VERSION 5.8 ;
BUSBITCHARS "[]" ;
DIVIDERCHAR "/" ;
UNITS
    DATABASE MICRONS 1000 ;
END UNITS

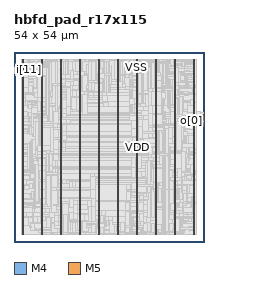
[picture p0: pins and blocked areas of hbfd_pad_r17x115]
MACRO hbfd_pad_r17x115
  FOREIGN hbfd_pad_r17x115 0 0 ;
  CLASS BLOCK ;
  SIZE 54 BY 54 ;
  PIN ck
    DIRECTION INPUT ;
    USE SIGNAL ;
    PORT
      LAYER M4 ;
        RECT  0 47.856 0.084 47.88 ;
    END
  END ck
  PIN i[0]
    DIRECTION INPUT ;
    USE SIGNAL ;
    PORT
      LAYER M4 ;
        RECT  0 47.952 0.084 47.976 ;
    END
  END i[0]
  PIN i[10]
    DIRECTION INPUT ;
    USE SIGNAL ;
    PORT
      LAYER M4 ;
        RECT  0 48.912 0.084 48.936 ;
    END
  END i[10]
  PIN i[11]
    DIRECTION INPUT ;
    USE SIGNAL ;
    PORT
      LAYER M4 ;
        RECT  0 49.008 0.084 49.032 ;
    END
  END i[11]
  PIN i[12]
    DIRECTION INPUT ;
    USE SIGNAL ;
    PORT
      LAYER M4 ;
        RECT  0 49.104 0.084 49.128 ;
    END
  END i[12]
  PIN i[13]
    DIRECTION INPUT ;
    USE SIGNAL ;
    PORT
      LAYER M4 ;
        RECT  0 49.2 0.084 49.224 ;
    END
  END i[13]
  PIN i[14]
    DIRECTION INPUT ;
    USE SIGNAL ;
    PORT
      LAYER M4 ;
        RECT  0 49.296 0.084 49.32 ;
    END
  END i[14]
  PIN i[15]
    DIRECTION INPUT ;
    USE SIGNAL ;
    PORT
      LAYER M4 ;
        RECT  0 49.392 0.084 49.416 ;
    END
  END i[15]
  PIN i[16]
    DIRECTION INPUT ;
    USE SIGNAL ;
    PORT
      LAYER M4 ;
        RECT  0 49.488 0.084 49.512 ;
    END
  END i[16]
  PIN i[1]
    DIRECTION INPUT ;
    USE SIGNAL ;
    PORT
      LAYER M4 ;
        RECT  0 48.048 0.084 48.072 ;
    END
  END i[1]
  PIN i[2]
    DIRECTION INPUT ;
    USE SIGNAL ;
    PORT
      LAYER M4 ;
        RECT  0 48.144 0.084 48.168 ;
    END
  END i[2]
  PIN i[3]
    DIRECTION INPUT ;
    USE SIGNAL ;
    PORT
      LAYER M4 ;
        RECT  0 48.24 0.084 48.264 ;
    END
  END i[3]
  PIN i[4]
    DIRECTION INPUT ;
    USE SIGNAL ;
    PORT
      LAYER M4 ;
        RECT  0 48.336 0.084 48.36 ;
    END
  END i[4]
  PIN i[5]
    DIRECTION INPUT ;
    USE SIGNAL ;
    PORT
      LAYER M4 ;
        RECT  0 48.432 0.084 48.456 ;
    END
  END i[5]
  PIN i[6]
    DIRECTION INPUT ;
    USE SIGNAL ;
    PORT
      LAYER M4 ;
        RECT  0 48.528 0.084 48.552 ;
    END
  END i[6]
  PIN i[7]
    DIRECTION INPUT ;
    USE SIGNAL ;
    PORT
      LAYER M4 ;
        RECT  0 48.624 0.084 48.648 ;
    END
  END i[7]
  PIN i[8]
    DIRECTION INPUT ;
    USE SIGNAL ;
    PORT
      LAYER M4 ;
        RECT  0 48.72 0.084 48.744 ;
    END
  END i[8]
  PIN i[9]
    DIRECTION INPUT ;
    USE SIGNAL ;
    PORT
      LAYER M4 ;
        RECT  0 48.816 0.084 48.84 ;
    END
  END i[9]
  PIN o[0]
    DIRECTION OUTPUT ;
    USE SIGNAL ;
    PORT
      LAYER M4 ;
        RECT  53.916 34.608 54 34.632 ;
    END
  END o[0]
  PIN o[10]
    DIRECTION OUTPUT ;
    USE SIGNAL ;
    PORT
      LAYER M4 ;
        RECT  53.916 35.568 54 35.592 ;
    END
  END o[10]
  PIN o[11]
    DIRECTION OUTPUT ;
    USE SIGNAL ;
    PORT
      LAYER M4 ;
        RECT  53.916 35.664 54 35.688 ;
    END
  END o[11]
  PIN o[12]
    DIRECTION OUTPUT ;
    USE SIGNAL ;
    PORT
      LAYER M4 ;
        RECT  53.916 35.76 54 35.784 ;
    END
  END o[12]
  PIN o[13]
    DIRECTION OUTPUT ;
    USE SIGNAL ;
    PORT
      LAYER M4 ;
        RECT  53.916 35.856 54 35.88 ;
    END
  END o[13]
  PIN o[14]
    DIRECTION OUTPUT ;
    USE SIGNAL ;
    PORT
      LAYER M4 ;
        RECT  53.916 35.952 54 35.976 ;
    END
  END o[14]
  PIN o[15]
    DIRECTION OUTPUT ;
    USE SIGNAL ;
    PORT
      LAYER M4 ;
        RECT  53.916 36.048 54 36.072 ;
    END
  END o[15]
  PIN o[16]
    DIRECTION OUTPUT ;
    USE SIGNAL ;
    PORT
      LAYER M4 ;
        RECT  53.916 36.144 54 36.168 ;
    END
  END o[16]
  PIN o[1]
    DIRECTION OUTPUT ;
    USE SIGNAL ;
    PORT
      LAYER M4 ;
        RECT  53.916 34.704 54 34.728 ;
    END
  END o[1]
  PIN o[2]
    DIRECTION OUTPUT ;
    USE SIGNAL ;
    PORT
      LAYER M4 ;
        RECT  53.916 34.8 54 34.824 ;
    END
  END o[2]
  PIN o[3]
    DIRECTION OUTPUT ;
    USE SIGNAL ;
    PORT
      LAYER M4 ;
        RECT  53.916 34.896 54 34.92 ;
    END
  END o[3]
  PIN o[4]
    DIRECTION OUTPUT ;
    USE SIGNAL ;
    PORT
      LAYER M4 ;
        RECT  53.916 34.992 54 35.016 ;
    END
  END o[4]
  PIN o[5]
    DIRECTION OUTPUT ;
    USE SIGNAL ;
    PORT
      LAYER M4 ;
        RECT  53.916 35.088 54 35.112 ;
    END
  END o[5]
  PIN o[6]
    DIRECTION OUTPUT ;
    USE SIGNAL ;
    PORT
      LAYER M4 ;
        RECT  53.916 35.184 54 35.208 ;
    END
  END o[6]
  PIN o[7]
    DIRECTION OUTPUT ;
    USE SIGNAL ;
    PORT
      LAYER M4 ;
        RECT  53.916 35.28 54 35.304 ;
    END
  END o[7]
  PIN o[8]
    DIRECTION OUTPUT ;
    USE SIGNAL ;
    PORT
      LAYER M4 ;
        RECT  53.916 35.376 54 35.4 ;
    END
  END o[8]
  PIN o[9]
    DIRECTION OUTPUT ;
    USE SIGNAL ;
    PORT
      LAYER M4 ;
        RECT  53.916 35.472 54 35.496 ;
    END
  END o[9]
  PIN rs
    DIRECTION INPUT ;
    USE SIGNAL ;
    PORT
      LAYER M4 ;
        RECT  0 49.584 0.084 49.608 ;
    END
  END rs
  PIN VDD
    DIRECTION INOUT ;
    USE POWER ;
    PORT
      LAYER M5 ;
        RECT  51.192 2.151 51.312 51.849 ;
        RECT  45.792 2.151 45.912 51.849 ;
        RECT  40.392 2.151 40.512 51.849 ;
        RECT  34.992 2.151 35.112 51.849 ;
        RECT  29.592 2.151 29.712 51.849 ;
        RECT  24.192 2.151 24.312 51.849 ;
        RECT  18.792 2.151 18.912 51.849 ;
        RECT  13.392 2.151 13.512 51.849 ;
        RECT  7.992 2.151 8.112 51.849 ;
        RECT  2.592 2.151 2.712 51.849 ;
    END
  END VDD
  PIN VSS
    DIRECTION INOUT ;
    USE GROUND ;
    PORT
      LAYER M5 ;
        RECT  51 2.137 51.12 51.863 ;
        RECT  45.6 2.137 45.72 51.863 ;
        RECT  40.2 2.137 40.32 51.863 ;
        RECT  34.8 2.137 34.92 51.863 ;
        RECT  29.4 2.137 29.52 51.863 ;
        RECT  24 2.137 24.12 51.863 ;
        RECT  18.6 2.137 18.72 51.863 ;
        RECT  13.2 2.137 13.32 51.863 ;
        RECT  7.8 2.137 7.92 51.863 ;
        RECT  2.4 2.137 2.52 51.863 ;
    END
  END VSS
  # OT_OBS_CLOSED layer=M5 d_um=1.536 added=289
  OBS
    LAYER RVTN ;
     RECT  2.16 2.16 51.84 2.295 ;
     RECT  2.16 2.565 51.84 2.835 ;
     RECT  2.16 3.105 51.84 3.375 ;
     RECT  2.16 3.645 51.84 3.915 ;
     RECT  2.16 4.185 51.84 4.455 ;
     RECT  2.16 4.725 51.84 4.995 ;
     RECT  2.16 5.265 51.84 5.535 ;
     RECT  2.16 5.805 51.84 6.075 ;
     RECT  2.16 6.345 51.84 6.615 ;
     RECT  2.16 6.885 51.84 7.155 ;
     RECT  2.16 7.425 51.84 7.695 ;
     RECT  2.16 7.965 51.84 8.235 ;
     RECT  2.16 8.505 51.84 8.775 ;
     RECT  2.16 9.045 51.84 9.315 ;
     RECT  2.16 9.585 51.84 9.855 ;
     RECT  2.16 10.125 51.84 10.395 ;
     RECT  2.16 10.665 51.84 10.935 ;
     RECT  2.16 11.205 51.84 11.475 ;
     RECT  2.16 11.745 51.84 12.015 ;
     RECT  2.16 12.285 51.84 12.555 ;
     RECT  2.16 12.825 51.84 13.095 ;
     RECT  2.16 13.365 51.84 13.635 ;
     RECT  2.16 13.905 51.84 14.175 ;
     RECT  2.16 14.445 51.84 14.715 ;
     RECT  2.16 14.985 51.84 15.255 ;
     RECT  2.16 15.525 51.84 15.795 ;
     RECT  2.16 16.065 51.84 16.335 ;
     RECT  2.16 16.605 51.84 16.875 ;
     RECT  2.16 17.145 51.84 17.415 ;
     RECT  2.16 17.685 51.84 17.955 ;
     RECT  2.16 18.225 51.84 18.495 ;
     RECT  2.16 18.765 51.84 19.035 ;
     RECT  2.16 19.305 51.84 19.575 ;
     RECT  2.16 19.845 51.84 20.115 ;
     RECT  2.16 20.385 51.84 20.655 ;
     RECT  2.16 20.925 51.84 21.195 ;
     RECT  2.16 21.465 51.84 21.735 ;
     RECT  2.16 22.005 51.84 22.275 ;
     RECT  2.16 22.545 51.84 22.815 ;
     RECT  2.16 23.085 51.84 23.355 ;
     RECT  2.16 23.625 51.84 23.895 ;
     RECT  2.16 24.165 51.84 24.435 ;
     RECT  2.16 24.705 51.84 24.975 ;
     RECT  2.16 25.245 51.84 25.515 ;
     RECT  2.16 25.785 51.84 26.055 ;
     RECT  2.16 26.325 51.84 26.595 ;
     RECT  2.16 26.865 51.84 27.135 ;
     RECT  2.16 27.405 51.84 27.675 ;
     RECT  2.16 27.945 51.84 28.215 ;
     RECT  2.16 28.485 51.84 28.755 ;
     RECT  2.16 29.025 51.84 29.295 ;
     RECT  2.16 29.565 51.84 29.835 ;
     RECT  2.16 30.105 51.84 30.375 ;
     RECT  2.16 30.645 51.84 30.915 ;
     RECT  2.16 31.185 51.84 31.455 ;
     RECT  2.16 31.725 51.84 31.995 ;
     RECT  2.16 32.265 51.84 32.535 ;
     RECT  2.16 32.805 51.84 33.075 ;
     RECT  2.16 33.345 51.84 33.615 ;
     RECT  2.16 33.885 51.84 34.155 ;
     RECT  2.16 34.425 51.84 34.695 ;
     RECT  2.16 34.965 51.84 35.235 ;
     RECT  2.16 35.505 51.84 35.775 ;
     RECT  2.16 36.045 51.84 36.315 ;
     RECT  2.16 36.585 51.84 36.855 ;
     RECT  2.16 37.125 51.84 37.395 ;
     RECT  2.16 37.665 51.84 37.935 ;
     RECT  2.16 38.205 51.84 38.475 ;
     RECT  2.16 38.745 51.84 39.015 ;
     RECT  2.16 39.285 51.84 39.555 ;
     RECT  2.16 39.825 51.84 40.095 ;
     RECT  2.16 40.365 51.84 40.635 ;
     RECT  2.16 40.905 51.84 41.175 ;
     RECT  2.16 41.445 51.84 41.715 ;
     RECT  2.16 41.985 51.84 42.255 ;
     RECT  2.16 42.525 51.84 42.795 ;
     RECT  2.16 43.065 51.84 43.335 ;
     RECT  2.16 43.605 51.84 43.875 ;
     RECT  2.16 44.145 51.84 44.415 ;
     RECT  2.16 44.685 51.84 44.955 ;
     RECT  2.16 45.225 51.84 45.495 ;
     RECT  2.16 45.765 51.84 46.035 ;
     RECT  2.16 46.305 51.84 46.575 ;
     RECT  2.16 46.845 51.84 47.115 ;
     RECT  2.16 47.385 51.84 47.655 ;
     RECT  2.16 47.925 51.84 48.195 ;
     RECT  2.16 48.465 51.84 48.735 ;
     RECT  2.16 49.005 51.84 49.275 ;
     RECT  2.16 49.545 51.84 49.815 ;
     RECT  2.16 50.085 51.84 50.355 ;
     RECT  2.16 50.625 51.84 50.895 ;
     RECT  2.16 51.165 51.84 51.435 ;
     RECT  2.16 51.705 51.84 51.84 ;
    LAYER RVTP ;
     RECT  2.16 2.295 51.84 2.565 ;
     RECT  2.16 2.835 51.84 3.105 ;
     RECT  2.16 3.375 51.84 3.645 ;
     RECT  2.16 3.915 51.84 4.185 ;
     RECT  2.16 4.455 51.84 4.725 ;
     RECT  2.16 4.995 51.84 5.265 ;
     RECT  2.16 5.535 51.84 5.805 ;
     RECT  2.16 6.075 51.84 6.345 ;
     RECT  2.16 6.615 51.84 6.885 ;
     RECT  2.16 7.155 51.84 7.425 ;
     RECT  2.16 7.695 51.84 7.965 ;
     RECT  2.16 8.235 51.84 8.505 ;
     RECT  2.16 8.775 51.84 9.045 ;
     RECT  2.16 9.315 51.84 9.585 ;
     RECT  2.16 9.855 51.84 10.125 ;
     RECT  2.16 10.395 51.84 10.665 ;
     RECT  2.16 10.935 51.84 11.205 ;
     RECT  2.16 11.475 51.84 11.745 ;
     RECT  2.16 12.015 51.84 12.285 ;
     RECT  2.16 12.555 51.84 12.825 ;
     RECT  2.16 13.095 51.84 13.365 ;
     RECT  2.16 13.635 51.84 13.905 ;
     RECT  2.16 14.175 51.84 14.445 ;
     RECT  2.16 14.715 51.84 14.985 ;
     RECT  2.16 15.255 51.84 15.525 ;
     RECT  2.16 15.795 51.84 16.065 ;
     RECT  2.16 16.335 51.84 16.605 ;
     RECT  2.16 16.875 51.84 17.145 ;
     RECT  2.16 17.415 51.84 17.685 ;
     RECT  2.16 17.955 51.84 18.225 ;
     RECT  2.16 18.495 51.84 18.765 ;
     RECT  2.16 19.035 51.84 19.305 ;
     RECT  2.16 19.575 51.84 19.845 ;
     RECT  2.16 20.115 51.84 20.385 ;
     RECT  2.16 20.655 51.84 20.925 ;
     RECT  2.16 21.195 51.84 21.465 ;
     RECT  2.16 21.735 51.84 22.005 ;
     RECT  2.16 22.275 51.84 22.545 ;
     RECT  2.16 22.815 51.84 23.085 ;
     RECT  2.16 23.355 51.84 23.625 ;
     RECT  2.16 23.895 51.84 24.165 ;
     RECT  2.16 24.435 51.84 24.705 ;
     RECT  2.16 24.975 51.84 25.245 ;
     RECT  2.16 25.515 51.84 25.785 ;
     RECT  2.16 26.055 51.84 26.325 ;
     RECT  2.16 26.595 51.84 26.865 ;
     RECT  2.16 27.135 51.84 27.405 ;
     RECT  2.16 27.675 51.84 27.945 ;
     RECT  2.16 28.215 51.84 28.485 ;
     RECT  2.16 28.755 51.84 29.025 ;
     RECT  2.16 29.295 51.84 29.565 ;
     RECT  2.16 29.835 51.84 30.105 ;
     RECT  2.16 30.375 51.84 30.645 ;
     RECT  2.16 30.915 51.84 31.185 ;
     RECT  2.16 31.455 51.84 31.725 ;
     RECT  2.16 31.995 51.84 32.265 ;
     RECT  2.16 32.535 51.84 32.805 ;
     RECT  2.16 33.075 51.84 33.345 ;
     RECT  2.16 33.615 51.84 33.885 ;
     RECT  2.16 34.155 51.84 34.425 ;
     RECT  2.16 34.695 51.84 34.965 ;
     RECT  2.16 35.235 51.84 35.505 ;
     RECT  2.16 35.775 51.84 36.045 ;
     RECT  2.16 36.315 51.84 36.585 ;
     RECT  2.16 36.855 51.84 37.125 ;
     RECT  2.16 37.395 51.84 37.665 ;
     RECT  2.16 37.935 51.84 38.205 ;
     RECT  2.16 38.475 51.84 38.745 ;
     RECT  2.16 39.015 51.84 39.285 ;
     RECT  2.16 39.555 51.84 39.825 ;
     RECT  2.16 40.095 51.84 40.365 ;
     RECT  2.16 40.635 51.84 40.905 ;
     RECT  2.16 41.175 51.84 41.445 ;
     RECT  2.16 41.715 51.84 41.985 ;
     RECT  2.16 42.255 51.84 42.525 ;
     RECT  2.16 42.795 51.84 43.065 ;
     RECT  2.16 43.335 51.84 43.605 ;
     RECT  2.16 43.875 51.84 44.145 ;
     RECT  2.16 44.415 51.84 44.685 ;
     RECT  2.16 44.955 51.84 45.225 ;
     RECT  2.16 45.495 51.84 45.765 ;
     RECT  2.16 46.035 51.84 46.305 ;
     RECT  2.16 46.575 51.84 46.845 ;
     RECT  2.16 47.115 51.84 47.385 ;
     RECT  2.16 47.655 51.84 47.925 ;
     RECT  2.16 48.195 51.84 48.465 ;
     RECT  2.16 48.735 51.84 49.005 ;
     RECT  2.16 49.275 51.84 49.545 ;
     RECT  2.16 49.815 51.84 50.085 ;
     RECT  2.16 50.355 51.84 50.625 ;
     RECT  2.16 50.895 51.84 51.165 ;
     RECT  2.16 51.435 51.84 51.705 ;
    LAYER M1 ;
     RECT  2.16 2.151 51.84 51.849 ;
    LAYER M2 ;
     RECT  0.103 47.862 0.499 47.88 ;
     RECT  0.499 47.736 0.535 47.88 ;
     RECT  0.535 47.466 2.16 48.456 ;
     RECT  2.16 2.151 18.823 51.849 ;
     RECT  18.823 2.106 24.251 51.849 ;
     RECT  24.251 2.151 29.083 51.849 ;
     RECT  29.083 2.106 37.067 51.849 ;
     RECT  37.067 2.151 51.84 51.849 ;
     RECT  51.84 34.164 52.979 37.044 ;
     RECT  52.979 34.164 53.015 36.774 ;
     RECT  53.015 36.018 53.051 36.774 ;
     RECT  53.015 34.164 53.087 34.758 ;
     RECT  53.051 36.054 53.843 36.774 ;
     RECT  53.843 36.126 53.879 36.774 ;
     RECT  53.087 34.164 53.915 34.182 ;
     RECT  53.879 36.126 53.915 36.144 ;
    LAYER M3 ;
     RECT  18.828 2.101 18.846 2.143 ;
     RECT  24.228 2.101 24.246 2.143 ;
     RECT  29.088 2.101 29.106 2.143 ;
     RECT  7.815 2.143 7.905 2.191 ;
     RECT  18.615 2.143 18.846 2.191 ;
     RECT  24.015 2.143 24.246 2.191 ;
     RECT  16.668 2.191 16.686 2.227 ;
     RECT  22.356 2.191 22.374 2.227 ;
     RECT  34.815 2.143 34.905 2.227 ;
     RECT  40.215 2.143 40.305 2.227 ;
     RECT  45.615 2.143 45.705 2.227 ;
     RECT  22.212 2.227 23.058 2.251 ;
     RECT  23.976 2.191 24.246 2.251 ;
     RECT  16.344 2.227 16.686 2.263 ;
     RECT  22.212 2.251 23.13 2.263 ;
     RECT  23.976 2.251 24.39 2.263 ;
     RECT  37.044 2.101 37.062 2.263 ;
     RECT  40.215 2.227 40.338 2.263 ;
     RECT  45.615 2.227 46.17 2.263 ;
     RECT  29.088 2.143 29.505 2.293 ;
     RECT  28.656 2.293 29.505 2.299 ;
     RECT  30.348 2.101 30.366 2.299 ;
     RECT  36.324 2.263 37.062 2.299 ;
     RECT  40.215 2.263 40.554 2.299 ;
     RECT  31.608 2.263 31.626 2.335 ;
     RECT  7.596 2.191 7.905 2.371 ;
     RECT  10.26 2.191 10.278 2.371 ;
     RECT  13.215 2.143 13.305 2.371 ;
     RECT  15.84 2.263 16.686 2.371 ;
     RECT  18.252 2.191 18.846 2.371 ;
     RECT  31.464 2.335 31.626 2.371 ;
     RECT  32.544 2.227 32.562 2.371 ;
     RECT  34.236 2.227 34.905 2.371 ;
     RECT  40.14 2.299 40.554 2.371 ;
     RECT  45.615 2.263 46.314 2.371 ;
     RECT  2.415 2.143 2.505 2.413 ;
     RECT  51.015 2.143 51.105 2.413 ;
     RECT  33.372 2.371 35.334 2.443 ;
     RECT  36.324 2.299 37.638 2.443 ;
     RECT  15.228 2.371 16.686 2.461 ;
     RECT  18.252 2.371 18.954 2.461 ;
     RECT  45.615 2.371 46.818 2.461 ;
     RECT  25.704 2.371 26.37 2.488 ;
     RECT  27.288 2.299 27.306 2.488 ;
     RECT  28.656 2.299 30.366 2.491 ;
     RECT  33.372 2.443 37.638 2.497 ;
     RECT  40.14 2.371 43.29 2.497 ;
     RECT  10.26 2.371 10.566 2.533 ;
     RECT  11.448 2.497 11.466 2.533 ;
     RECT  31.464 2.371 32.562 2.533 ;
     RECT  33.372 2.497 37.746 2.533 ;
     RECT  39.888 2.497 43.29 2.533 ;
     RECT  45.615 2.461 47.43 2.533 ;
     RECT  38.736 2.497 38.754 2.569 ;
     RECT  39.6 2.533 43.29 2.569 ;
     RECT  45.615 2.533 48.222 2.569 ;
     RECT  7.452 2.371 8.37 2.605 ;
     RECT  9.216 2.371 9.234 2.605 ;
     RECT  12.276 2.461 12.294 2.605 ;
     RECT  13.215 2.371 14.022 2.605 ;
     RECT  20.268 2.497 20.286 2.605 ;
     RECT  21.708 2.263 24.39 2.605 ;
     RECT  25.704 2.488 27.306 2.605 ;
     RECT  44.172 2.461 44.19 2.605 ;
     RECT  45.615 2.569 48.474 2.605 ;
     RECT  6.948 2.605 9.234 2.641 ;
     RECT  10.26 2.533 11.466 2.641 ;
     RECT  12.276 2.605 14.022 2.641 ;
     RECT  15.228 2.461 18.954 2.641 ;
     RECT  19.728 2.605 20.286 2.641 ;
     RECT  21.528 2.605 24.39 2.641 ;
     RECT  25.524 2.605 27.306 2.641 ;
     RECT  28.224 2.491 30.366 2.641 ;
     RECT  31.464 2.533 37.746 2.641 ;
     RECT  38.736 2.569 43.29 2.641 ;
     RECT  44.172 2.605 48.474 2.641 ;
     RECT  12.204 2.641 43.29 2.731 ;
     RECT  44.172 2.641 48.582 2.731 ;
     RECT  6.948 2.641 11.466 2.767 ;
     RECT  12.204 2.731 48.582 2.767 ;
     RECT  6.948 2.767 48.582 3.145 ;
     RECT  49.86 2.875 49.878 3.145 ;
     RECT  51.015 2.413 51.297 3.145 ;
     RECT  5.328 3.145 5.346 3.181 ;
     RECT  6.588 3.145 48.654 3.181 ;
     RECT  49.86 3.145 51.297 3.181 ;
     RECT  5.328 3.181 48.654 3.343 ;
     RECT  4.788 3.343 48.798 3.371 ;
     RECT  5.724 3.371 48.798 3.451 ;
     RECT  49.752 3.181 51.297 3.451 ;
     RECT  4.788 3.371 4.806 4.225 ;
     RECT  4.428 4.225 4.806 4.261 ;
     RECT  4.428 4.261 4.878 4.379 ;
     RECT  4.428 4.379 4.59 4.765 ;
     RECT  4.032 4.765 4.59 4.829 ;
     RECT  4.572 4.829 4.59 5.197 ;
     RECT  5.724 3.451 51.297 5.197 ;
     RECT  4.572 5.197 51.297 5.837 ;
     RECT  4.572 5.837 49.554 5.999 ;
     RECT  3.708 5.575 3.726 6.043 ;
     RECT  3.564 6.043 3.726 6.283 ;
     RECT  2.415 2.413 2.697 6.547 ;
     RECT  3.564 6.283 4.014 6.547 ;
     RECT  4.752 5.999 49.554 6.781 ;
     RECT  50.328 5.837 51.297 6.781 ;
     RECT  2.415 6.547 4.014 7.051 ;
     RECT  4.752 6.781 51.297 7.051 ;
     RECT  2.415 7.051 51.297 7.349 ;
     RECT  2.415 7.349 2.697 8.509 ;
     RECT  3.564 7.349 51.297 8.509 ;
     RECT  2.415 8.509 51.297 9.787 ;
     RECT  2.376 9.787 51.297 10.895 ;
     RECT  2.415 10.895 51.297 11.011 ;
     RECT  2.415 11.011 51.714 11.201 ;
     RECT  2.415 11.201 51.354 12.209 ;
     RECT  2.415 12.209 51.297 13.675 ;
     RECT  2.376 13.675 51.297 13.829 ;
     RECT  2.415 13.829 51.297 16.141 ;
     RECT  2.415 16.141 51.354 16.367 ;
     RECT  2.415 16.367 51.297 17.491 ;
     RECT  2.415 17.491 51.714 17.681 ;
     RECT  2.415 17.681 51.297 19.039 ;
     RECT  2.415 19.039 51.39 19.309 ;
     RECT  2.415 19.309 51.534 19.651 ;
     RECT  2.415 19.651 51.714 19.921 ;
     RECT  2.376 19.921 51.714 20.381 ;
     RECT  2.376 20.381 51.297 20.615 ;
     RECT  2.415 20.615 51.297 24.241 ;
     RECT  2.376 24.241 51.297 24.943 ;
     RECT  2.304 24.943 51.297 25.285 ;
     RECT  2.304 25.285 51.714 25.439 ;
     RECT  2.304 25.439 51.297 26.401 ;
     RECT  2.304 26.401 51.714 26.663 ;
     RECT  2.304 26.663 51.297 30.749 ;
     RECT  2.376 30.749 51.297 32.035 ;
     RECT  2.376 32.035 51.354 32.225 ;
     RECT  2.415 32.225 51.354 32.369 ;
     RECT  2.415 32.369 51.297 32.971 ;
     RECT  2.376 32.971 51.297 33.053 ;
     RECT  2.415 33.053 51.297 33.277 ;
     RECT  2.415 33.277 51.318 33.449 ;
     RECT  53.892 34.159 53.91 34.637 ;
     RECT  52.452 34.501 52.47 34.663 ;
     RECT  52.416 34.663 52.47 34.733 ;
     RECT  52.452 34.733 52.47 34.735 ;
     RECT  52.452 34.735 53.082 34.829 ;
     RECT  52.452 34.829 53.01 34.925 ;
     RECT  2.415 33.449 51.297 34.969 ;
     RECT  2.415 34.969 51.318 35.117 ;
     RECT  52.956 34.925 53.01 35.563 ;
     RECT  2.415 35.117 51.297 35.581 ;
     RECT  2.376 35.581 51.297 35.699 ;
     RECT  53.82 35.467 53.838 35.851 ;
     RECT  52.956 35.563 53.046 35.947 ;
     RECT  52.416 35.947 53.046 36.041 ;
     RECT  53.82 35.851 53.91 36.077 ;
     RECT  53.856 36.077 53.91 36.149 ;
     RECT  52.416 36.041 53.01 36.239 ;
     RECT  52.956 36.239 53.01 36.509 ;
     RECT  53.856 36.149 53.874 36.779 ;
     RECT  2.415 35.699 51.297 36.931 ;
     RECT  52.956 36.509 52.974 37.049 ;
     RECT  2.376 36.931 51.297 38.669 ;
     RECT  2.415 38.669 51.297 39.595 ;
     RECT  2.415 39.595 51.714 39.749 ;
     RECT  2.415 39.749 51.297 40.027 ;
     RECT  2.376 40.027 51.297 40.289 ;
     RECT  2.415 40.289 51.297 41.791 ;
     RECT  2.415 41.791 51.354 42.061 ;
     RECT  2.415 42.061 51.462 42.179 ;
     RECT  2.415 42.179 51.297 43.645 ;
     RECT  2.415 43.645 51.39 43.915 ;
     RECT  2.415 43.915 51.534 44.339 ;
     RECT  2.415 44.339 51.39 44.375 ;
     RECT  2.415 44.375 51.297 44.491 ;
     RECT  2.376 44.491 51.297 45.455 ;
     RECT  2.415 45.455 51.297 45.535 ;
     RECT  2.415 45.535 51.354 46.139 ;
     RECT  2.415 46.139 51.297 47.155 ;
     RECT  2.34 47.155 51.297 47.579 ;
     RECT  3.78 47.579 51.297 47.687 ;
     RECT  0.54 47.461 0.558 47.731 ;
     RECT  0.504 47.731 0.558 47.857 ;
     RECT  2.34 47.579 2.898 47.885 ;
     RECT  7.416 47.687 51.297 47.885 ;
     RECT  0.108 47.857 0.558 47.981 ;
     RECT  3.78 47.687 6.642 47.993 ;
     RECT  0.504 47.981 0.558 48.173 ;
     RECT  2.34 47.885 2.826 48.235 ;
     RECT  26.964 47.885 51.297 48.425 ;
     RECT  3.924 47.993 6.642 48.469 ;
     RECT  7.416 47.885 26.226 48.469 ;
     RECT  0.54 48.173 0.558 48.557 ;
     RECT  3.924 48.469 26.226 48.811 ;
     RECT  2.304 48.235 2.826 48.937 ;
     RECT  3.636 48.811 26.226 48.937 ;
     RECT  2.304 48.937 26.226 49.099 ;
     RECT  27 48.425 51.297 49.199 ;
     RECT  2.268 49.099 26.226 49.307 ;
     RECT  2.304 49.307 26.226 49.315 ;
     RECT  27 49.199 48.402 49.315 ;
     RECT  2.304 49.315 48.402 49.775 ;
     RECT  2.34 49.775 48.402 49.906 ;
     RECT  45.288 49.906 48.402 49.963 ;
     RECT  49.212 49.199 51.297 49.963 ;
     RECT  2.34 49.906 44.514 50.153 ;
     RECT  2.34 50.153 44.37 50.315 ;
     RECT  45.288 49.963 51.297 50.521 ;
     RECT  45.288 50.521 51.354 50.701 ;
     RECT  45.216 50.701 51.39 50.819 ;
     RECT  2.376 50.315 44.37 50.963 ;
     RECT  3.708 50.963 25.794 51.089 ;
     RECT  26.784 50.963 44.37 51.089 ;
     RECT  2.376 50.963 2.697 51.149 ;
     RECT  3.708 51.089 25.722 51.233 ;
     RECT  26.892 51.089 44.37 51.241 ;
     RECT  3.708 51.233 15.57 51.293 ;
     RECT  26.892 51.241 44.442 51.341 ;
     RECT  3.708 51.293 15.534 51.359 ;
     RECT  16.416 51.233 25.722 51.359 ;
     RECT  32.724 51.341 44.442 51.359 ;
     RECT  45.216 50.819 51.297 51.359 ;
     RECT  5.544 51.359 5.814 51.395 ;
     RECT  14.544 51.359 15.426 51.395 ;
     RECT  26.892 51.341 31.986 51.395 ;
     RECT  16.668 51.359 19.242 51.437 ;
     RECT  6.912 51.359 8.226 51.467 ;
     RECT  29.016 51.395 31.914 51.467 ;
     RECT  42.192 51.359 42.354 51.503 ;
     RECT  45.468 51.359 51.297 51.503 ;
     RECT  21.204 51.359 25.722 51.539 ;
     RECT  34.092 51.359 41.418 51.539 ;
     RECT  2.415 51.149 2.697 51.587 ;
     RECT  29.016 51.467 30.33 51.587 ;
     RECT  45.468 51.503 47.61 51.587 ;
     RECT  51.015 51.503 51.297 51.587 ;
     RECT  3.708 51.359 4.734 51.629 ;
     RECT  5.544 51.395 5.562 51.629 ;
     RECT  7.056 51.467 8.226 51.629 ;
     RECT  9 51.359 12.438 51.629 ;
     RECT  14.544 51.395 15.39 51.629 ;
     RECT  19.98 51.359 20.214 51.629 ;
     RECT  21.276 51.539 25.722 51.629 ;
     RECT  27.036 51.395 28.242 51.629 ;
     RECT  29.016 51.587 29.505 51.629 ;
     RECT  32.724 51.359 33.318 51.629 ;
     RECT  34.092 51.539 39.078 51.629 ;
     RECT  39.888 51.539 41.418 51.629 ;
     RECT  42.192 51.503 42.21 51.629 ;
     RECT  48.492 51.503 50.13 51.629 ;
     RECT  27.432 51.629 28.098 51.635 ;
     RECT  11.052 51.629 12.366 51.665 ;
     RECT  14.544 51.629 15.246 51.665 ;
     RECT  16.776 51.437 19.242 51.665 ;
     RECT  23.112 51.629 25.614 51.665 ;
     RECT  27.432 51.635 27.774 51.665 ;
     RECT  31.104 51.467 31.806 51.665 ;
     RECT  43.236 51.359 44.442 51.665 ;
     RECT  49.176 51.629 50.13 51.665 ;
     RECT  23.112 51.665 25.47 51.677 ;
     RECT  45.468 51.587 45.705 51.677 ;
     RECT  46.584 51.587 47.61 51.677 ;
     RECT  49.392 51.665 49.698 51.701 ;
     RECT  16.776 51.665 18.705 51.737 ;
     RECT  23.112 51.677 23.13 51.737 ;
     RECT  24.015 51.677 24.354 51.737 ;
     RECT  25.128 51.677 25.47 51.737 ;
     RECT  30.312 51.587 30.33 51.737 ;
     RECT  9 51.629 9.666 51.773 ;
     RECT  11.16 51.665 12.366 51.773 ;
     RECT  27.432 51.665 27.45 51.773 ;
     RECT  34.668 51.629 34.905 51.773 ;
     RECT  35.748 51.629 35.766 51.773 ;
     RECT  36.684 51.629 36.702 51.773 ;
     RECT  41.4 51.629 41.418 51.773 ;
     RECT  43.884 51.665 44.442 51.773 ;
     RECT  7.056 51.629 7.905 51.809 ;
     RECT  9 51.773 9.018 51.809 ;
     RECT  11.484 51.773 11.502 51.809 ;
     RECT  13.215 51.359 13.77 51.809 ;
     RECT  16.776 51.737 17.442 51.809 ;
     RECT  25.452 51.737 25.47 51.809 ;
     RECT  31.788 51.665 31.806 51.809 ;
     RECT  37.62 51.629 37.638 51.809 ;
     RECT  47.052 51.677 47.61 51.809 ;
     RECT  49.68 51.701 49.698 51.809 ;
     RECT  2.415 51.587 2.505 51.857 ;
     RECT  7.815 51.809 7.905 51.857 ;
     RECT  13.215 51.809 13.305 51.857 ;
     RECT  18.615 51.737 18.705 51.857 ;
     RECT  24.015 51.737 24.105 51.857 ;
     RECT  29.415 51.629 29.505 51.857 ;
     RECT  34.815 51.773 34.905 51.857 ;
     RECT  40.215 51.629 40.305 51.857 ;
     RECT  45.615 51.677 45.705 51.857 ;
     RECT  51.015 51.587 51.105 51.857 ;
    LAYER M4 ;
     RECT  2.365 13.68 2.408 13.704 ;
     RECT  2.401 26.112 2.408 26.136 ;
     RECT  2.365 27.888 2.408 27.912 ;
     RECT  2.365 33.024 2.408 33.048 ;
     RECT  2.365 40.032 2.408 40.056 ;
     RECT  0.084 47.856 2.408 47.88 ;
     RECT  0.06 47.88 2.408 47.952 ;
     RECT  0.084 47.952 2.408 47.976 ;
     RECT  0.06 47.976 2.408 48.048 ;
     RECT  0.084 48.048 2.408 48.072 ;
     RECT  0.06 48.072 2.408 48.144 ;
     RECT  0.084 48.144 2.408 48.168 ;
     RECT  0.06 48.168 2.408 48.24 ;
     RECT  0.084 48.24 2.408 48.264 ;
     RECT  0.06 48.264 2.408 48.336 ;
     RECT  0.084 48.336 2.408 48.36 ;
     RECT  0.06 48.36 2.408 48.432 ;
     RECT  0.084 48.432 2.408 48.456 ;
     RECT  0.06 48.456 2.408 48.528 ;
     RECT  0.084 48.528 2.408 48.552 ;
     RECT  0.06 48.552 2.408 48.624 ;
     RECT  0.084 48.624 2.408 48.648 ;
     RECT  0.06 48.648 2.408 48.72 ;
     RECT  0.084 48.72 2.408 48.744 ;
     RECT  0.06 48.744 2.408 48.816 ;
     RECT  0.084 48.816 2.408 48.84 ;
     RECT  0.06 48.84 2.408 48.912 ;
     RECT  0.084 48.912 2.408 48.936 ;
     RECT  0.06 48.936 2.408 49.008 ;
     RECT  0.084 49.008 2.408 49.032 ;
     RECT  0.06 49.032 2.408 49.104 ;
     RECT  0.084 49.104 2.408 49.128 ;
     RECT  0.06 49.128 2.408 49.2 ;
     RECT  0.084 49.2 2.408 49.224 ;
     RECT  0.06 49.224 2.408 49.296 ;
     RECT  0.084 49.296 2.408 49.32 ;
     RECT  0.06 49.32 2.408 49.392 ;
     RECT  0.084 49.392 2.408 49.416 ;
     RECT  0.06 49.416 2.408 49.488 ;
     RECT  0.084 49.488 2.408 49.512 ;
     RECT  0.06 49.512 2.408 49.584 ;
     RECT  0.084 49.584 2.408 49.608 ;
     RECT  2.365 51.12 2.408 51.144 ;
     RECT  2.408 2.148 2.512 51.852 ;
     RECT  2.512 2.418 2.704 51.582 ;
     RECT  2.704 47.328 2.801 50.136 ;
     RECT  2.704 26.112 2.819 26.808 ;
     RECT  2.819 26.112 2.837 26.76 ;
     RECT  2.704 14.832 2.917 16.44 ;
     RECT  2.917 15.984 2.953 16.44 ;
     RECT  2.704 38.736 3.299 41.064 ;
     RECT  2.704 42.048 3.436 42.216 ;
     RECT  2.704 33.024 3.629 33.048 ;
     RECT  2.704 35.568 3.701 37.176 ;
     RECT  3.299 38.736 3.701 40.296 ;
     RECT  2.917 14.832 3.733 14.856 ;
     RECT  2.704 27.84 3.733 27.912 ;
     RECT  2.704 51.12 3.737 51.144 ;
     RECT  2.704 30.72 3.769 31.368 ;
     RECT  2.704 10.224 3.773 10.536 ;
     RECT  2.837 26.256 3.805 26.76 ;
     RECT  2.704 20.496 3.877 21.528 ;
     RECT  2.704 22.752 3.877 24.36 ;
     RECT  3.805 25.44 3.877 26.76 ;
     RECT  3.733 27.84 3.877 28.008 ;
     RECT  3.733 14.784 3.881 14.856 ;
     RECT  3.697 5.616 3.913 5.64 ;
     RECT  2.801 47.328 3.932 47.88 ;
     RECT  3.701 38.736 3.949 39 ;
     RECT  2.801 49.2 3.949 50.136 ;
     RECT  3.913 5.616 3.973 6.6 ;
     RECT  3.932 46.752 3.973 47.88 ;
     RECT  3.881 14.832 3.985 14.856 ;
     RECT  2.704 34.176 3.985 34.248 ;
     RECT  3.985 14.832 3.989 15.336 ;
     RECT  3.701 35.568 3.989 36.456 ;
     RECT  3.973 4.8 4.019 7.08 ;
     RECT  3.973 46.752 4.019 48.072 ;
     RECT  3.436 42.192 4.021 42.216 ;
     RECT  2.704 43.296 4.021 44.904 ;
     RECT  4.019 47.76 4.06 48.072 ;
     RECT  4.019 4.8 4.061 4.824 ;
     RECT  3.949 49.2 4.061 50.904 ;
     RECT  3.949 38.208 4.093 39 ;
     RECT  4.021 42.192 4.093 44.904 ;
     RECT  4.093 42.192 4.115 45.48 ;
     RECT  3.985 34.08 4.129 34.248 ;
     RECT  3.989 35.568 4.129 35.592 ;
     RECT  4.061 50.112 4.133 50.904 ;
     RECT  4.115 42.192 4.169 44.472 ;
     RECT  3.769 30.72 4.237 31.656 ;
     RECT  4.201 32.832 4.237 32.856 ;
     RECT  4.093 38.16 4.237 39 ;
     RECT  3.989 15.312 4.273 15.336 ;
     RECT  2.953 16.416 4.273 16.44 ;
     RECT  2.704 17.856 4.273 18.84 ;
     RECT  4.237 30.72 4.273 32.856 ;
     RECT  3.877 20.496 4.309 28.008 ;
     RECT  4.273 17.856 4.345 19.32 ;
     RECT  4.019 6.288 4.385 7.08 ;
     RECT  2.704 12.192 4.385 12.36 ;
     RECT  4.273 15.312 4.417 16.44 ;
     RECT  2.704 13.68 4.453 13.704 ;
     RECT  4.129 34.08 4.457 35.592 ;
     RECT  4.457 35.424 4.493 35.592 ;
     RECT  3.701 40.272 4.565 40.296 ;
     RECT  3.773 10.512 4.669 10.536 ;
     RECT  4.345 17.712 4.705 19.32 ;
     RECT  4.309 20.496 4.705 28.44 ;
     RECT  4.385 12.24 4.741 12.36 ;
     RECT  4.453 13.632 4.741 13.704 ;
     RECT  4.741 12.24 4.957 13.704 ;
     RECT  4.237 37.968 4.957 39 ;
     RECT  4.705 17.712 5.065 28.44 ;
     RECT  4.457 34.08 5.077 34.2 ;
     RECT  4.957 37.968 5.077 39.72 ;
     RECT  4.273 30.672 5.101 32.856 ;
     RECT  5.077 37.584 5.123 39.72 ;
     RECT  4.06 47.76 5.125 47.88 ;
     RECT  5.123 37.584 5.137 38.184 ;
     RECT  5.125 47.76 5.171 48.216 ;
     RECT  4.417 15.312 5.173 16.584 ;
     RECT  5.065 17.712 5.177 29.064 ;
     RECT  5.137 37.344 5.213 38.184 ;
     RECT  5.101 30.624 5.245 32.856 ;
     RECT  5.101 8.304 5.324 8.328 ;
     RECT  4.169 42.432 5.353 44.472 ;
     RECT  4.385 6.288 5.365 6.312 ;
     RECT  4.133 50.496 5.365 50.904 ;
     RECT  5.245 30.096 5.381 32.856 ;
     RECT  5.324 7.584 5.411 8.328 ;
     RECT  5.213 37.344 5.413 37.944 ;
     RECT  5.365 5.664 5.425 6.312 ;
     RECT  4.669 10.512 5.425 10.728 ;
     RECT  4.957 12.24 5.425 14.232 ;
     RECT  5.171 47.856 5.425 48.216 ;
     RECT  5.353 41.712 5.465 44.472 ;
     RECT  5.173 15.312 5.533 16.728 ;
     RECT  5.177 17.712 5.533 23.64 ;
     RECT  5.365 50.496 5.573 51.336 ;
     RECT  5.465 43.92 5.605 44.472 ;
     RECT  4.115 45.456 5.605 45.48 ;
     RECT  4.417 46.512 5.605 46.536 ;
     RECT  5.425 10.512 5.641 14.232 ;
     RECT  5.381 30.096 5.641 33.048 ;
     RECT  5.077 34.032 5.641 34.2 ;
     RECT  5.533 15.312 5.645 23.64 ;
     RECT  5.123 39.168 5.749 39.72 ;
     RECT  5.425 47.856 5.749 48.696 ;
     RECT  5.641 9.84 5.797 14.232 ;
     RECT  5.797 9.456 5.821 14.232 ;
     RECT  5.645 15.312 5.821 22.008 ;
     RECT  5.465 41.712 5.857 42.456 ;
     RECT  5.573 50.496 5.861 50.904 ;
     RECT  5.411 8.304 5.889 8.328 ;
     RECT  5.177 24.864 6.001 29.064 ;
     RECT  5.641 30.096 6.001 34.2 ;
     RECT  5.821 9.456 6.005 22.008 ;
     RECT  6.005 9.456 6.113 10.104 ;
     RECT  5.749 39.168 6.113 39.768 ;
     RECT  6.005 11.376 6.149 22.008 ;
     RECT  6.113 39.264 6.217 39.768 ;
     RECT  5.645 23.04 6.253 23.64 ;
     RECT  6.253 23.04 6.289 23.784 ;
     RECT  5.605 43.92 6.289 46.536 ;
     RECT  5.749 47.856 6.289 49.08 ;
     RECT  6.217 39.264 6.365 39.816 ;
     RECT  6.037 3.84 6.401 3.864 ;
     RECT  4.493 35.424 6.469 35.448 ;
     RECT  5.413 36.624 6.469 37.944 ;
     RECT  5.425 5.664 6.649 7.224 ;
     RECT  6.289 43.92 6.649 49.08 ;
     RECT  6.649 43.824 6.653 49.08 ;
     RECT  6.289 23.04 6.685 23.88 ;
     RECT  6.469 35.424 6.721 37.944 ;
     RECT  6.653 46.56 6.757 49.08 ;
     RECT  5.857 41.04 6.793 42.456 ;
     RECT  5.861 50.688 6.805 50.904 ;
     RECT  6.149 11.52 6.865 22.008 ;
     RECT  6.685 22.992 6.865 23.88 ;
     RECT  6.865 11.52 6.901 23.88 ;
     RECT  6.001 24.864 6.901 34.2 ;
     RECT  6.721 35.184 6.901 37.944 ;
     RECT  6.653 43.824 6.937 45.576 ;
     RECT  6.793 41.04 6.973 42.792 ;
     RECT  6.901 11.52 7.117 37.944 ;
     RECT  6.365 39.312 7.261 39.816 ;
     RECT  6.973 40.896 7.261 42.792 ;
     RECT  7.117 11.232 7.333 37.944 ;
     RECT  7.261 39.312 7.333 42.792 ;
     RECT  6.649 5.616 7.405 7.368 ;
     RECT  6.113 9.792 7.441 10.104 ;
     RECT  7.405 5.616 7.477 7.752 ;
     RECT  7.441 9.696 7.477 10.2 ;
     RECT  7.333 11.232 7.477 42.792 ;
     RECT  6.757 46.56 7.513 49.56 ;
     RECT  6.805 50.688 7.513 51.336 ;
     RECT  7.477 9.696 7.657 42.792 ;
     RECT  7.657 9.264 7.765 42.792 ;
     RECT  7.369 3.936 7.808 3.96 ;
     RECT  7.477 5.28 7.808 7.752 ;
     RECT  7.765 8.976 7.808 42.792 ;
     RECT  6.937 43.776 7.808 45.576 ;
     RECT  7.513 46.56 7.808 51.336 ;
     RECT  7.808 2.148 7.912 51.852 ;
     RECT  7.912 2.418 8.104 51.582 ;
     RECT  8.104 3.936 8.165 7.368 ;
     RECT  8.104 50.544 8.309 51.24 ;
     RECT  8.309 50.544 8.777 51.192 ;
     RECT  8.777 50.832 8.993 51.192 ;
     RECT  8.165 4.08 9.133 7.368 ;
     RECT  8.104 8.496 9.133 49.512 ;
     RECT  9.133 4.08 9.137 49.512 ;
     RECT  9.137 19.968 9.925 49.512 ;
     RECT  8.993 50.832 9.925 51 ;
     RECT  9.925 19.968 10.109 51 ;
     RECT  9.137 4.08 10.465 18.792 ;
     RECT  10.465 3.408 10.501 18.792 ;
     RECT  10.109 39.504 10.537 51 ;
     RECT  10.501 3.168 10.753 18.792 ;
     RECT  10.537 39.504 10.789 51.144 ;
     RECT  10.109 19.968 10.825 38.472 ;
     RECT  10.825 19.872 11.689 38.472 ;
     RECT  10.789 39.504 11.689 51.24 ;
     RECT  10.753 2.64 12.229 18.792 ;
     RECT  11.689 19.872 12.229 51.24 ;
     RECT  12.229 2.64 13.208 51.24 ;
     RECT  13.208 2.148 13.312 51.852 ;
     RECT  13.312 2.418 13.504 51.582 ;
     RECT  13.504 2.784 14.033 51.24 ;
     RECT  14.033 39.072 14.749 51.24 ;
     RECT  14.033 2.784 15.217 37.992 ;
     RECT  14.749 39.072 15.217 51.288 ;
     RECT  15.217 2.784 15.581 51.288 ;
     RECT  15.581 2.784 16.657 51.24 ;
     RECT  16.657 2.784 17.417 51.432 ;
     RECT  17.417 2.784 17.564 51.384 ;
     RECT  17.564 2.688 18.608 51.384 ;
     RECT  18.608 2.148 18.712 51.852 ;
     RECT  18.712 2.418 18.904 51.582 ;
     RECT  18.904 2.88 19.253 51.384 ;
     RECT  19.253 2.88 19.469 51.288 ;
     RECT  19.469 2.88 21.229 51.24 ;
     RECT  21.229 2.832 21.913 51.24 ;
     RECT  21.913 2.832 23.029 51.288 ;
     RECT  23.029 2.496 23.101 51.288 ;
     RECT  23.101 2.256 23.425 51.288 ;
     RECT  23.425 2.256 24.008 51.672 ;
     RECT  24.008 2.148 24.112 51.852 ;
     RECT  24.112 2.256 24.401 51.672 ;
     RECT  24.401 2.352 24.581 51.672 ;
     RECT  24.581 2.352 25.337 51.24 ;
     RECT  25.337 2.352 25.804 51.192 ;
     RECT  25.804 4.464 26.237 51.192 ;
     RECT  26.237 4.752 26.953 51.192 ;
     RECT  25.804 2.352 27.277 3.384 ;
     RECT  26.953 4.752 27.277 51.24 ;
     RECT  27.277 2.352 28.645 51.624 ;
     RECT  28.645 2.304 29.408 51.624 ;
     RECT  29.408 2.148 29.512 51.852 ;
     RECT  29.512 2.304 29.704 51.582 ;
     RECT  29.704 2.304 30.017 51.24 ;
     RECT  30.017 2.352 30.233 51.24 ;
     RECT  30.233 2.88 30.341 51.24 ;
     RECT  30.341 3.024 30.769 51.24 ;
     RECT  30.769 3.024 31.381 51.336 ;
     RECT  31.381 2.784 31.453 51.336 ;
     RECT  31.453 2.736 32.753 51.336 ;
     RECT  32.753 2.736 33.037 51.24 ;
     RECT  33.037 2.544 33.221 51.24 ;
     RECT  33.221 2.784 33.473 51.24 ;
     RECT  33.473 2.88 33.797 51.24 ;
     RECT  33.797 2.88 34.808 3.432 ;
     RECT  33.797 4.416 34.808 51.24 ;
     RECT  34.808 2.148 34.912 51.852 ;
     RECT  34.912 2.418 35.104 51.582 ;
     RECT  35.104 2.448 35.273 51.24 ;
     RECT  35.273 2.448 35.885 3.576 ;
     RECT  35.885 2.832 35.891 3.576 ;
     RECT  35.273 4.656 36.245 51.24 ;
     RECT  35.891 2.88 36.277 3.576 ;
     RECT  36.245 4.656 36.277 50.856 ;
     RECT  36.277 2.88 36.497 50.856 ;
     RECT  36.497 2.928 36.707 50.856 ;
     RECT  36.707 50.592 37.249 50.856 ;
     RECT  37.249 50.592 37.757 51.096 ;
     RECT  36.707 2.928 37.825 49.608 ;
     RECT  37.825 2.88 38.909 49.608 ;
     RECT  38.909 17.136 38.977 49.608 ;
     RECT  37.757 50.688 38.977 51.096 ;
     RECT  38.909 2.88 39.193 16.152 ;
     RECT  39.193 2.784 39.884 16.152 ;
     RECT  38.977 17.136 39.884 51.096 ;
     RECT  39.884 2.784 40.069 51.096 ;
     RECT  40.069 2.256 40.208 51.096 ;
     RECT  40.208 2.148 40.312 51.852 ;
     RECT  40.312 2.256 40.349 51.582 ;
     RECT  40.349 2.418 40.504 51.582 ;
     RECT  40.504 2.784 40.673 51.24 ;
     RECT  40.673 2.832 40.925 51.24 ;
     RECT  40.925 2.832 41.105 50.856 ;
     RECT  41.105 16.08 41.357 50.856 ;
     RECT  41.105 2.832 41.929 15.096 ;
     RECT  41.929 2.64 42.073 15.096 ;
     RECT  41.357 16.08 42.073 50.712 ;
     RECT  42.073 2.64 42.257 50.712 ;
     RECT  42.257 45.12 42.433 50.712 ;
     RECT  42.257 2.64 42.617 44.136 ;
     RECT  42.617 2.64 42.653 37.224 ;
     RECT  42.617 38.688 42.653 44.136 ;
     RECT  42.653 33.552 43.013 37.224 ;
     RECT  42.653 2.64 43.121 32.376 ;
     RECT  43.013 33.552 43.157 36.696 ;
     RECT  42.433 45.12 43.196 50.856 ;
     RECT  42.653 44.112 43.225 44.136 ;
     RECT  43.196 45.12 43.225 51.624 ;
     RECT  43.225 44.112 43.283 51.624 ;
     RECT  42.653 38.688 43.621 43.08 ;
     RECT  43.283 44.112 43.697 50.856 ;
     RECT  43.121 3.024 43.801 32.376 ;
     RECT  43.157 33.552 43.801 34.968 ;
     RECT  43.697 48.24 43.841 50.856 ;
     RECT  43.621 38.208 43.873 43.08 ;
     RECT  43.801 3.024 43.877 34.968 ;
     RECT  43.873 38.016 43.909 43.08 ;
     RECT  43.877 28.416 43.913 34.968 ;
     RECT  43.697 44.112 44.021 46.584 ;
     RECT  43.909 38.016 44.089 43.128 ;
     RECT  43.157 36.336 44.161 36.696 ;
     RECT  44.089 37.968 44.161 43.128 ;
     RECT  43.877 3.024 44.165 27.096 ;
     RECT  44.165 3.024 44.201 20.424 ;
     RECT  43.841 48.24 44.201 48.984 ;
     RECT  44.021 44.16 44.237 46.584 ;
     RECT  44.165 21.552 44.345 27.096 ;
     RECT  43.841 50.016 44.381 50.856 ;
     RECT  43.913 33.648 44.485 34.968 ;
     RECT  44.161 36.336 44.485 43.128 ;
     RECT  44.485 33.648 44.489 43.128 ;
     RECT  44.237 44.16 44.525 46.296 ;
     RECT  44.381 50.016 44.525 50.136 ;
     RECT  44.525 50.016 45.025 50.04 ;
     RECT  43.913 28.416 45.061 32.52 ;
     RECT  44.489 39.024 45.061 43.128 ;
     RECT  44.525 44.16 45.061 46.104 ;
     RECT  44.201 3.024 45.241 7.8 ;
     RECT  44.201 8.832 45.241 20.424 ;
     RECT  45.241 3.024 45.608 20.424 ;
     RECT  44.345 21.552 45.608 26.856 ;
     RECT  45.061 27.888 45.608 32.52 ;
     RECT  44.489 33.648 45.608 38.04 ;
     RECT  45.061 39.024 45.608 46.104 ;
     RECT  44.201 48.24 45.608 48.408 ;
     RECT  45.025 49.872 45.608 50.04 ;
     RECT  45.457 51.648 45.608 51.672 ;
     RECT  45.608 2.148 45.712 51.852 ;
     RECT  45.712 2.418 45.904 51.672 ;
     RECT  45.904 3.024 45.929 29.064 ;
     RECT  45.929 7.968 46.181 29.064 ;
     RECT  46.181 9.84 46.217 29.064 ;
     RECT  45.904 36.336 46.361 50.04 ;
     RECT  45.904 30.048 46.397 35.16 ;
     RECT  46.217 9.84 46.433 23.064 ;
     RECT  46.217 24.192 46.469 29.064 ;
     RECT  45.904 51.456 46.613 51.672 ;
     RECT  46.433 9.84 46.749 22.872 ;
     RECT  46.361 36.336 46.787 44.328 ;
     RECT  46.361 45.408 46.793 50.04 ;
     RECT  46.613 51.456 46.897 51.48 ;
     RECT  46.749 9.84 46.937 19.992 ;
     RECT  46.897 51.36 46.937 51.48 ;
     RECT  46.787 36.336 46.972 44.136 ;
     RECT  46.749 20.976 47.045 22.872 ;
     RECT  46.972 42.528 47.045 44.136 ;
     RECT  45.929 3.024 47.077 6.648 ;
     RECT  46.181 7.968 47.077 8.856 ;
     RECT  47.077 3.024 47.164 8.856 ;
     RECT  46.793 45.408 47.261 48.264 ;
     RECT  47.045 43.92 47.333 44.136 ;
     RECT  47.164 3.024 47.441 6.84 ;
     RECT  46.793 49.44 47.477 50.04 ;
     RECT  47.441 4.176 47.549 6.84 ;
     RECT  46.469 24.24 47.581 29.064 ;
     RECT  47.333 44.112 47.693 44.136 ;
     RECT  46.397 30.144 47.797 35.16 ;
     RECT  46.972 36.336 47.797 41.352 ;
     RECT  47.581 23.856 47.833 29.064 ;
     RECT  47.797 30.144 47.833 41.352 ;
     RECT  46.937 51.36 47.833 51.384 ;
     RECT  47.164 7.92 47.852 8.856 ;
     RECT  46.937 9.84 47.852 18.552 ;
     RECT  47.477 50.016 47.905 50.04 ;
     RECT  47.833 51.168 47.905 51.384 ;
     RECT  47.852 7.92 47.909 18.552 ;
     RECT  47.909 7.92 47.939 16.152 ;
     RECT  47.549 4.176 47.945 6.744 ;
     RECT  47.945 5.28 47.987 6.744 ;
     RECT  47.939 9.744 48.017 16.152 ;
     RECT  47.833 23.856 48.017 41.352 ;
     RECT  47.939 7.92 48.053 8.472 ;
     RECT  47.045 20.976 48.085 22.584 ;
     RECT  47.261 48.24 48.125 48.264 ;
     RECT  48.017 27.888 48.161 41.352 ;
     RECT  48.161 27.888 48.233 39.816 ;
     RECT  47.045 42.528 48.233 42.792 ;
     RECT  47.987 5.28 48.269 6.648 ;
     RECT  48.161 41.328 48.269 41.352 ;
     RECT  48.017 9.744 48.275 13.704 ;
     RECT  46.937 19.536 48.305 19.992 ;
     RECT  48.233 35.04 48.305 39.816 ;
     RECT  47.909 17.472 48.377 18.552 ;
     RECT  47.261 45.984 48.409 47.256 ;
     RECT  47.905 50.016 48.476 51.384 ;
     RECT  47.441 3.024 48.485 3.048 ;
     RECT  48.269 5.28 48.485 6.12 ;
     RECT  48.409 45.6 48.517 47.256 ;
     RECT  48.476 49.968 48.521 51.384 ;
     RECT  48.521 49.968 48.563 51.288 ;
     RECT  48.233 27.888 48.593 33.624 ;
     RECT  48.563 50.016 48.629 51.288 ;
     RECT  48.305 35.04 48.701 36.552 ;
     RECT  48.193 44.208 48.709 44.232 ;
     RECT  48.517 45.6 48.709 47.4 ;
     RECT  48.305 19.728 48.729 19.992 ;
     RECT  48.593 27.888 48.809 31.704 ;
     RECT  48.709 44.208 48.917 47.4 ;
     RECT  48.377 17.568 48.953 18.552 ;
     RECT  48.485 5.28 48.989 5.496 ;
     RECT  48.809 27.888 49.025 31.512 ;
     RECT  48.275 10.512 49.043 13.704 ;
     RECT  48.085 20.976 49.045 23.544 ;
     RECT  48.017 24.96 49.045 26.76 ;
     RECT  48.953 17.568 49.061 18.024 ;
     RECT  49.045 20.976 49.061 26.76 ;
     RECT  48.017 14.736 49.093 16.152 ;
     RECT  48.053 7.92 49.165 7.944 ;
     RECT  49.043 11.376 49.165 13.704 ;
     RECT  49.093 14.736 49.165 16.44 ;
     RECT  49.165 11.376 49.205 16.44 ;
     RECT  49.165 7.92 49.237 8.328 ;
     RECT  48.917 44.208 49.241 47.304 ;
     RECT  48.305 37.584 49.283 39.768 ;
     RECT  48.701 35.136 49.324 35.88 ;
     RECT  49.283 37.584 49.324 37.608 ;
     RECT  49.205 13.68 49.349 16.44 ;
     RECT  49.237 7.104 49.385 8.328 ;
     RECT  49.025 31.488 49.385 31.512 ;
     RECT  49.241 44.208 49.457 45.576 ;
     RECT  49.061 17.568 49.493 17.976 ;
     RECT  49.025 27.888 49.529 30.264 ;
     RECT  48.629 50.88 49.529 51.288 ;
     RECT  48.373 41.568 49.561 41.592 ;
     RECT  48.233 42.768 49.561 42.792 ;
     RECT  49.561 41.568 49.601 42.792 ;
     RECT  49.529 27.888 49.637 30.216 ;
     RECT  49.601 42.192 49.637 42.792 ;
     RECT  49.637 27.888 49.673 28.776 ;
     RECT  47.945 4.176 49.705 4.2 ;
     RECT  49.061 21.984 49.709 26.76 ;
     RECT  49.457 44.208 49.741 44.232 ;
     RECT  49.709 23.232 49.745 26.76 ;
     RECT  49.741 43.92 49.745 44.232 ;
     RECT  48.949 48.624 49.781 48.648 ;
     RECT  49.349 13.824 49.817 16.44 ;
     RECT  49.745 23.232 49.889 24.552 ;
     RECT  49.916 31.968 49.957 31.992 ;
     RECT  48.593 33.024 49.957 33.624 ;
     RECT  48.729 19.728 50.065 19.752 ;
     RECT  49.283 38.832 50.101 39.768 ;
     RECT  50.065 19.584 50.173 19.752 ;
     RECT  49.309 20.832 50.173 20.856 ;
     RECT  50.173 19.584 50.209 20.856 ;
     RECT  49.709 21.984 50.209 22.008 ;
     RECT  49.205 11.376 50.425 12.552 ;
     RECT  49.385 7.92 50.461 8.328 ;
     RECT  49.241 46.752 50.485 47.304 ;
     RECT  50.485 46.656 50.497 47.304 ;
     RECT  49.493 17.568 50.533 17.592 ;
     RECT  50.533 6.768 50.569 6.792 ;
     RECT  49.324 35.136 50.569 35.832 ;
     RECT  50.137 10.224 50.581 10.248 ;
     RECT  50.425 11.376 50.581 12.84 ;
     RECT  50.581 10.224 50.636 12.84 ;
     RECT  49.957 31.968 50.785 33.624 ;
     RECT  49.637 42.192 50.821 42.6 ;
     RECT  49.745 43.92 50.821 43.944 ;
     RECT  49.705 4.176 51.008 4.296 ;
     RECT  48.989 5.28 51.008 5.304 ;
     RECT  50.569 6.768 51.008 6.888 ;
     RECT  50.461 7.92 51.008 8.472 ;
     RECT  50.636 9.552 51.008 12.84 ;
     RECT  49.817 13.824 51.008 16.152 ;
     RECT  50.533 17.568 51.008 18.504 ;
     RECT  50.209 19.584 51.008 22.008 ;
     RECT  49.889 23.712 51.008 24.552 ;
     RECT  49.745 25.584 51.008 26.76 ;
     RECT  49.673 27.888 51.008 27.912 ;
     RECT  49.637 30.144 51.008 30.216 ;
     RECT  50.785 31.92 51.008 33.624 ;
     RECT  50.569 34.752 51.008 35.832 ;
     RECT  50.101 38.832 51.008 40.44 ;
     RECT  50.821 42.192 51.008 43.944 ;
     RECT  49.457 45.552 51.008 45.576 ;
     RECT  50.497 46.656 51.008 47.736 ;
     RECT  49.529 50.88 51.008 51.24 ;
     RECT  51.008 2.148 51.112 51.852 ;
     RECT  51.112 2.418 51.304 51.582 ;
     RECT  51.304 35.088 52.405 35.112 ;
     RECT  52.405 34.704 52.981 35.976 ;
     RECT  52.981 34.704 53.881 36.168 ;
     RECT  53.881 34.608 53.916 34.632 ;
     RECT  53.881 34.632 53.964 34.704 ;
     RECT  53.881 34.704 53.916 34.728 ;
     RECT  53.881 34.728 53.964 34.8 ;
     RECT  53.881 34.8 53.916 34.824 ;
     RECT  53.881 34.824 53.964 34.896 ;
     RECT  53.881 34.896 53.916 34.92 ;
     RECT  53.881 34.92 53.964 34.992 ;
     RECT  53.881 34.992 53.916 35.016 ;
     RECT  53.881 35.016 53.964 35.088 ;
     RECT  53.881 35.088 53.916 35.112 ;
     RECT  53.881 35.112 53.964 35.184 ;
     RECT  53.881 35.184 53.916 35.208 ;
     RECT  53.881 35.208 53.964 35.28 ;
     RECT  53.881 35.28 53.916 35.304 ;
     RECT  53.881 35.304 53.964 35.376 ;
     RECT  53.881 35.376 53.916 35.4 ;
     RECT  53.881 35.4 53.964 35.472 ;
     RECT  53.881 35.472 53.916 35.496 ;
     RECT  53.881 35.496 53.964 35.568 ;
     RECT  53.881 35.568 53.916 35.592 ;
     RECT  53.881 35.592 53.964 35.664 ;
     RECT  53.881 35.664 53.916 35.688 ;
     RECT  53.881 35.688 53.964 35.76 ;
     RECT  53.881 35.76 53.916 35.784 ;
     RECT  53.881 35.784 53.964 35.856 ;
     RECT  53.881 35.856 53.916 35.88 ;
     RECT  53.881 35.88 53.964 35.952 ;
     RECT  53.881 35.952 53.916 35.976 ;
     RECT  53.881 35.976 53.964 36.048 ;
     RECT  53.881 36.048 53.916 36.072 ;
     RECT  53.881 36.072 53.964 36.144 ;
     RECT  53.881 36.144 53.916 36.168 ;
    LAYER M5 ;
     RECT  2.4 2.137 2.52 2.151 ;
     RECT  7.8 2.137 7.92 2.151 ;
     RECT  13.2 2.137 13.32 2.151 ;
     RECT  18.6 2.137 18.72 2.151 ;
     RECT  24 2.137 24.12 2.151 ;
     RECT  29.4 2.137 29.52 2.151 ;
     RECT  34.8 2.137 34.92 2.151 ;
     RECT  40.2 2.137 40.32 2.151 ;
     RECT  45.6 2.137 45.72 2.151 ;
     RECT  51 2.137 51.12 2.151 ;
     RECT  40.2 2.151 40.512 2.245 ;
     RECT  18.6 2.151 18.912 2.677 ;
     RECT  40.08 2.245 40.512 2.819 ;
     RECT  34.8 2.151 35.112 2.821 ;
     RECT  13.2 2.151 13.512 2.869 ;
     RECT  29.4 2.151 29.712 2.965 ;
     RECT  12.816 2.869 13.512 3.109 ;
     RECT  29.4 2.965 30.264 3.109 ;
     RECT  45.6 2.151 45.912 3.109 ;
     RECT  29.088 3.109 30.264 3.251 ;
     RECT  12.816 3.109 13.656 3.347 ;
     RECT  17.616 2.677 18.912 3.347 ;
     RECT  34.8 2.821 35.88 3.587 ;
     RECT  44.976 3.109 45.912 3.635 ;
     RECT  42.144 3.301 42.168 3.685 ;
     RECT  24 2.151 24.312 3.829 ;
     RECT  29.232 3.251 30.264 4.405 ;
     RECT  25.728 4.261 25.752 4.453 ;
     RECT  34.8 3.587 35.496 4.453 ;
     RECT  34.224 4.453 35.496 4.693 ;
     RECT  33.024 4.117 33.048 4.739 ;
     RECT  13.2 3.347 13.656 4.789 ;
     RECT  20.544 3.925 20.568 4.789 ;
     RECT  21.984 4.261 22.008 4.789 ;
     RECT  20.544 4.789 22.008 4.933 ;
     RECT  23.808 3.829 24.312 4.933 ;
     RECT  25.728 4.453 25.992 4.981 ;
     RECT  28.656 4.405 30.264 5.029 ;
     RECT  40.2 2.819 40.512 5.029 ;
     RECT  40.2 5.029 40.632 5.077 ;
     RECT  41.904 3.685 42.168 5.077 ;
     RECT  36.912 4.165 36.936 5.173 ;
     RECT  20.544 4.933 24.312 5.219 ;
     RECT  43.872 5.173 43.896 5.221 ;
     RECT  45.6 3.635 45.912 5.221 ;
     RECT  11.52 3.925 11.544 5.269 ;
     RECT  23.664 5.219 24.312 5.269 ;
     RECT  34.224 4.693 35.928 5.317 ;
     RECT  43.872 5.221 43.992 5.317 ;
     RECT  10.56 5.269 11.544 5.411 ;
     RECT  36.912 5.173 37.272 5.413 ;
     RECT  28.032 5.029 30.264 5.557 ;
     RECT  31.536 2.773 31.56 5.557 ;
     RECT  25.728 4.981 26.136 5.603 ;
     RECT  20.544 5.219 22.008 5.747 ;
     RECT  33.888 5.317 35.928 5.747 ;
     RECT  12.672 4.789 13.656 5.749 ;
     RECT  20.544 5.747 21.096 5.749 ;
     RECT  17.088 5.605 17.112 5.843 ;
     RECT  16.032 3.301 16.056 5.845 ;
     RECT  18.096 3.347 18.912 5.845 ;
     RECT  20.064 5.749 21.096 5.845 ;
     RECT  15.456 5.845 16.056 5.987 ;
     RECT  18.096 5.845 21.096 5.987 ;
     RECT  25.968 5.603 26.136 6.037 ;
     RECT  38.88 5.317 38.904 6.037 ;
     RECT  7.8 2.151 8.112 6.133 ;
     RECT  38.88 6.037 39.096 6.227 ;
     RECT  43.776 5.317 43.992 6.275 ;
     RECT  44.976 5.221 45.912 6.323 ;
     RECT  23.664 5.269 24.408 6.421 ;
     RECT  48.24 5.461 48.264 6.709 ;
     RECT  43.776 6.275 43.896 6.755 ;
     RECT  38.88 6.227 38.904 6.899 ;
     RECT  3.984 4.789 4.008 7.091 ;
     RECT  12.576 5.749 13.656 7.093 ;
     RECT  33.888 5.747 35.64 7.093 ;
     RECT  45.504 6.323 45.912 7.139 ;
     RECT  43.776 6.755 43.8 7.235 ;
     RECT  36.912 5.413 37.656 7.237 ;
     RECT  25.968 6.037 26.76 7.285 ;
     RECT  28.032 5.557 31.56 7.285 ;
     RECT  33.168 7.093 35.64 7.379 ;
     RECT  7.8 6.133 8.856 7.381 ;
     RECT  9.984 6.901 10.008 7.381 ;
     RECT  47.952 6.709 48.264 7.381 ;
     RECT  23.088 6.421 24.408 7.621 ;
     RECT  12.576 7.093 13.896 7.667 ;
     RECT  7.8 7.381 10.008 7.717 ;
     RECT  15.648 5.987 15.672 7.909 ;
     RECT  51 2.151 51.312 7.909 ;
     RECT  18.096 5.987 20.088 7.957 ;
     RECT  21.072 5.987 21.096 7.957 ;
     RECT  33.36 7.379 35.64 8.003 ;
     RECT  47.088 7.381 48.264 8.003 ;
     RECT  18.096 7.957 21.096 8.005 ;
     RECT  36.912 7.237 37.8 8.245 ;
     RECT  5.376 5.653 5.4 8.293 ;
     RECT  11.52 5.411 11.544 8.435 ;
     RECT  7.488 7.717 10.008 8.437 ;
     RECT  7.488 8.437 10.536 8.483 ;
     RECT  15.408 7.909 15.672 8.485 ;
     RECT  16.8 6.421 16.824 8.485 ;
     RECT  33.36 8.003 35.4 8.485 ;
     RECT  33.168 8.485 35.4 8.531 ;
     RECT  33.168 8.531 35.304 8.725 ;
     RECT  36.912 8.245 37.848 8.821 ;
     RECT  23.088 7.621 24.888 8.869 ;
     RECT  25.968 7.285 31.56 8.869 ;
     RECT  33.024 8.725 35.304 8.963 ;
     RECT  36.576 8.821 37.848 8.963 ;
     RECT  44.448 9.061 44.472 9.109 ;
     RECT  18 8.005 21.096 9.155 ;
     RECT  12.72 7.667 13.896 9.349 ;
     RECT  40.2 5.077 42.168 9.349 ;
     RECT  43.968 9.109 44.472 9.395 ;
     RECT  7.488 8.483 8.904 9.445 ;
     RECT  9.984 8.483 10.536 9.445 ;
     RECT  5.376 8.293 5.832 9.491 ;
     RECT  15.408 8.485 16.824 9.731 ;
     RECT  40.08 9.349 42.168 9.731 ;
     RECT  7.488 9.445 10.536 10.067 ;
     RECT  12.144 9.349 13.896 10.067 ;
     RECT  33.168 8.963 35.304 10.069 ;
     RECT  40.08 9.731 42.12 10.115 ;
     RECT  5.376 9.491 5.4 10.501 ;
     RECT  47.904 8.003 48.264 10.501 ;
     RECT  5.376 10.501 5.688 10.547 ;
     RECT  7.488 10.067 9.576 10.547 ;
     RECT  11.328 10.309 11.352 10.547 ;
     RECT  18 9.155 21 10.547 ;
     RECT  36.768 8.963 37.848 10.739 ;
     RECT  50.688 7.909 51.312 10.837 ;
     RECT  44.448 9.395 44.472 10.883 ;
     RECT  47.904 10.501 49.032 10.883 ;
     RECT  50.592 10.837 51.312 10.979 ;
     RECT  12.72 10.067 13.896 11.029 ;
     RECT  15.408 9.731 15.672 11.029 ;
     RECT  40.2 10.115 42.12 11.171 ;
     RECT  33.12 10.069 35.304 11.269 ;
     RECT  33.12 11.269 35.688 11.317 ;
     RECT  48.24 10.883 49.032 11.411 ;
     RECT  12.72 11.029 15.672 11.413 ;
     RECT  23.088 8.869 31.56 11.605 ;
     RECT  18.144 10.547 21 11.701 ;
     RECT  21.984 10.213 22.008 11.701 ;
     RECT  33.072 11.317 35.688 11.701 ;
     RECT  36.768 10.739 37.8 11.701 ;
     RECT  16.8 9.731 16.824 11.749 ;
     RECT  18.144 11.701 22.008 11.749 ;
     RECT  23.088 11.605 31.896 11.795 ;
     RECT  33.072 11.701 37.8 11.843 ;
     RECT  36.768 11.843 37.8 12.085 ;
     RECT  47.232 11.365 47.256 12.131 ;
     RECT  36.768 12.085 38.136 12.179 ;
     RECT  16.8 11.749 22.008 12.227 ;
     RECT  51 10.979 51.312 12.325 ;
     RECT  12.528 11.413 15.672 12.421 ;
     RECT  16.8 12.227 21.624 12.421 ;
     RECT  7.488 10.547 8.856 12.469 ;
     RECT  5.664 10.547 5.688 12.563 ;
     RECT  12.528 12.421 21.624 12.563 ;
     RECT  48.24 11.411 48.264 12.611 ;
     RECT  33.12 11.843 35.688 12.755 ;
     RECT  36.816 12.179 38.136 12.995 ;
     RECT  34.368 12.755 35.688 13.093 ;
     RECT  34.368 13.093 35.832 13.139 ;
     RECT  34.8 13.139 35.832 13.765 ;
     RECT  36.816 12.995 37.656 13.765 ;
     RECT  34.8 13.765 37.656 14.053 ;
     RECT  34.8 14.053 38.568 14.101 ;
     RECT  34.704 14.101 38.568 14.195 ;
     RECT  33.12 12.755 33.384 14.245 ;
     RECT  40.2 11.171 40.512 14.245 ;
     RECT  47.616 14.197 47.64 14.341 ;
     RECT  33.12 14.245 33.432 14.485 ;
     RECT  33.024 14.485 33.432 14.629 ;
     RECT  42.096 11.171 42.12 14.725 ;
     RECT  12.72 12.563 21.624 14.773 ;
     RECT  39.648 14.245 40.512 14.821 ;
     RECT  32.976 14.629 33.432 14.867 ;
     RECT  11.952 14.773 21.624 14.915 ;
     RECT  32.976 14.867 33.384 14.915 ;
     RECT  17.232 14.915 21.624 14.917 ;
     RECT  44.256 14.869 44.28 15.011 ;
     RECT  7.296 12.469 8.856 15.061 ;
     RECT  50.88 12.325 51.312 15.203 ;
     RECT  42.096 14.725 42.744 15.251 ;
     RECT  2.4 2.151 2.712 15.301 ;
     RECT  45.6 7.139 45.912 15.301 ;
     RECT  39.312 14.821 40.512 15.347 ;
     RECT  10.656 14.773 10.68 15.443 ;
     RECT  11.952 14.915 15.768 15.491 ;
     RECT  17.232 14.917 21.816 15.539 ;
     RECT  34.704 14.195 37.656 15.733 ;
     RECT  47.616 14.341 47.688 15.827 ;
     RECT  45.6 15.301 46.584 15.973 ;
     RECT  47.616 15.827 47.64 15.973 ;
     RECT  34.704 15.733 38.424 16.211 ;
     RECT  45.6 15.973 47.64 16.307 ;
     RECT  23.088 11.795 31.848 16.357 ;
     RECT  33.024 14.915 33.384 16.357 ;
     RECT  2.4 15.301 2.904 16.405 ;
     RECT  12.72 15.491 15.768 16.643 ;
     RECT  23.088 16.357 33.384 16.933 ;
     RECT  34.704 16.211 37.464 16.933 ;
     RECT  39.648 15.347 40.512 17.029 ;
     RECT  42.096 15.251 42.12 17.029 ;
     RECT  7.296 15.061 8.904 17.077 ;
     RECT  45.6 16.307 46.584 17.077 ;
     RECT  17.376 15.539 21.816 17.125 ;
     RECT  45.024 17.077 46.584 17.219 ;
     RECT  14.832 16.643 15.768 17.461 ;
     RECT  16.944 17.125 21.816 17.461 ;
     RECT  45.6 17.219 46.584 17.461 ;
     RECT  47.568 16.307 47.64 17.461 ;
     RECT  23.088 16.933 37.464 17.557 ;
     RECT  6.864 17.077 8.904 17.651 ;
     RECT  2.4 16.405 3.432 17.891 ;
     RECT  12.72 16.643 13.8 17.893 ;
     RECT  14.832 17.461 21.816 17.893 ;
     RECT  23.088 17.557 37.704 18.179 ;
     RECT  4.752 18.037 4.776 18.181 ;
     RECT  34.656 18.179 37.704 18.227 ;
     RECT  45.6 17.461 47.64 18.227 ;
     RECT  23.088 18.179 33.624 18.323 ;
     RECT  44.448 17.605 44.472 18.419 ;
     RECT  47.568 18.227 47.64 18.517 ;
     RECT  23.088 18.323 33.528 18.565 ;
     RECT  36.096 18.227 37.464 18.611 ;
     RECT  45.6 18.227 46.584 18.805 ;
     RECT  4.752 18.181 5.736 19.379 ;
     RECT  12.72 17.893 21.816 19.381 ;
     RECT  22.944 18.565 33.528 19.381 ;
     RECT  47.568 18.517 48.504 19.763 ;
     RECT  44.976 18.805 46.584 19.811 ;
     RECT  34.656 18.227 35.112 19.957 ;
     RECT  36.096 18.611 37.32 19.957 ;
     RECT  4.752 19.379 4.776 20.003 ;
     RECT  7.296 17.651 8.904 20.437 ;
     RECT  12.72 19.381 33.528 20.725 ;
     RECT  12.48 20.725 33.528 20.821 ;
     RECT  45.6 19.811 46.584 20.821 ;
     RECT  47.568 19.763 47.64 20.821 ;
     RECT  39.648 17.029 42.12 20.917 ;
     RECT  34.656 19.957 37.32 20.963 ;
     RECT  38.88 20.917 42.12 21.059 ;
     RECT  12.24 20.821 33.528 21.107 ;
     RECT  34.656 20.963 35.112 21.109 ;
     RECT  12.288 21.107 33.528 21.347 ;
     RECT  7.104 20.437 8.904 21.637 ;
     RECT  36.096 20.963 37.32 21.637 ;
     RECT  7.104 21.637 9.432 21.779 ;
     RECT  39.648 21.059 42.12 22.021 ;
     RECT  39.36 22.021 42.12 22.163 ;
     RECT  10.8 20.821 10.824 22.211 ;
     RECT  36.096 21.637 37.416 22.501 ;
     RECT  5.328 22.165 5.352 22.741 ;
     RECT  48.672 19.957 48.696 22.741 ;
     RECT  4.416 22.741 5.352 22.835 ;
     RECT  39.36 22.163 41.256 22.835 ;
     RECT  12.48 21.347 33.528 23.027 ;
     RECT  36.096 22.501 37.608 23.077 ;
     RECT  44.448 22.165 44.472 23.411 ;
     RECT  4.416 22.835 4.44 23.555 ;
     RECT  11.28 23.125 11.304 23.557 ;
     RECT  7.104 21.779 8.856 23.749 ;
     RECT  6.816 23.749 8.856 23.893 ;
     RECT  36.096 23.077 38.232 23.893 ;
     RECT  39.648 22.835 41.256 23.893 ;
     RECT  12.72 23.027 33.528 23.989 ;
     RECT  34.56 21.109 35.112 23.989 ;
     RECT  36.096 23.893 41.256 24.083 ;
     RECT  48.672 22.741 49.08 24.085 ;
     RECT  43.536 24.373 43.56 24.469 ;
     RECT  12.72 23.989 35.112 24.517 ;
     RECT  36.096 24.083 38.088 24.517 ;
     RECT  10.848 23.557 11.304 24.757 ;
     RECT  6.816 23.893 9.144 24.949 ;
     RECT  10.752 24.757 11.304 24.949 ;
     RECT  12.72 24.517 38.088 24.949 ;
     RECT  39.12 24.083 41.256 24.995 ;
     RECT  10.752 24.949 38.088 25.045 ;
     RECT  39.36 24.995 41.256 25.045 ;
     RECT  10.224 25.045 38.088 25.091 ;
     RECT  45.6 20.821 47.64 25.093 ;
     RECT  42.672 24.469 43.56 25.187 ;
     RECT  48.672 24.085 49.32 25.187 ;
     RECT  39.36 25.045 41.688 25.475 ;
     RECT  44.928 25.093 47.64 25.477 ;
     RECT  6.768 24.949 9.144 25.667 ;
     RECT  10.224 25.091 11.304 25.715 ;
     RECT  42.672 25.187 42.696 25.715 ;
     RECT  48.672 25.187 48.696 25.715 ;
     RECT  12.72 25.091 38.088 25.811 ;
     RECT  39.36 25.475 41.256 25.811 ;
     RECT  44.592 25.477 47.64 25.811 ;
     RECT  44.592 25.811 44.616 25.907 ;
     RECT  7.8 25.667 9.144 26.005 ;
     RECT  10.224 25.715 10.248 26.005 ;
     RECT  2.4 17.891 2.712 26.101 ;
     RECT  6.768 25.667 6.792 26.101 ;
     RECT  45.6 25.811 47.64 26.147 ;
     RECT  12.72 25.811 13.704 26.293 ;
     RECT  14.688 25.811 38.088 26.483 ;
     RECT  36.336 26.483 38.088 26.579 ;
     RECT  36.672 26.579 38.088 26.773 ;
     RECT  39.36 25.811 40.512 26.773 ;
     RECT  2.4 26.101 2.808 26.819 ;
     RECT  6.288 26.101 6.792 26.819 ;
     RECT  12.528 26.293 13.704 26.819 ;
     RECT  36.672 26.773 40.512 27.157 ;
     RECT  14.688 26.483 35.112 27.251 ;
     RECT  6.768 26.819 6.792 27.347 ;
     RECT  7.8 26.005 10.248 27.349 ;
     RECT  34.656 27.251 35.112 27.683 ;
     RECT  34.8 27.683 35.112 27.781 ;
     RECT  45.6 26.147 46.2 27.877 ;
     RECT  36.672 27.157 40.632 27.971 ;
     RECT  34.8 27.781 35.208 28.213 ;
     RECT  12.528 26.819 13.656 28.405 ;
     RECT  14.688 27.251 33.672 28.405 ;
     RECT  12.528 28.405 33.672 28.547 ;
     RECT  47.616 26.147 47.64 28.837 ;
     RECT  12.528 28.547 13.752 28.883 ;
     RECT  5.088 27.541 5.112 29.075 ;
     RECT  12.528 28.883 13.656 29.125 ;
     RECT  34.8 28.213 35.352 29.173 ;
     RECT  36.672 27.971 40.512 29.315 ;
     RECT  42.144 29.173 42.168 29.315 ;
     RECT  43.776 27.877 43.8 29.363 ;
     RECT  34.8 29.173 35.4 29.365 ;
     RECT  36.672 29.315 38.088 29.365 ;
     RECT  34.8 29.365 38.088 29.555 ;
     RECT  14.976 28.547 33.672 29.605 ;
     RECT  34.8 29.555 35.352 29.605 ;
     RECT  12.288 29.125 13.656 29.651 ;
     RECT  39.264 29.315 40.512 29.699 ;
     RECT  39.36 29.699 40.512 29.747 ;
     RECT  14.976 29.605 35.352 30.083 ;
     RECT  45.072 27.877 46.2 30.083 ;
     RECT  14.976 30.083 33.336 30.181 ;
     RECT  42.288 30.181 42.312 30.853 ;
     RECT  36.432 29.555 38.088 30.949 ;
     RECT  39.456 29.747 40.512 30.949 ;
     RECT  42.288 30.853 42.408 31.141 ;
     RECT  14.784 30.181 33.336 31.379 ;
     RECT  36.432 30.949 40.512 31.379 ;
     RECT  49.344 30.181 49.368 31.523 ;
     RECT  39.456 31.379 40.512 31.813 ;
     RECT  42.048 31.141 42.408 31.813 ;
     RECT  11.28 25.715 11.304 32.053 ;
     RECT  12.576 29.651 13.656 32.053 ;
     RECT  34.8 30.083 35.352 32.245 ;
     RECT  34.704 32.245 35.352 32.387 ;
     RECT  7.536 27.349 10.248 32.437 ;
     RECT  11.28 32.053 13.656 32.437 ;
     RECT  47.616 28.837 48.264 32.437 ;
     RECT  5.088 30.709 5.496 32.531 ;
     RECT  7.536 32.437 13.656 32.675 ;
     RECT  39.456 31.813 42.408 32.677 ;
     RECT  39.264 32.677 42.408 32.723 ;
     RECT  34.8 32.387 35.352 32.963 ;
     RECT  39.264 32.723 42.312 33.059 ;
     RECT  47.616 32.437 48.36 33.107 ;
     RECT  7.536 32.675 11.304 33.205 ;
     RECT  39.456 33.059 42.312 33.299 ;
     RECT  12.384 32.675 13.656 33.301 ;
     RECT  14.976 31.379 33.336 33.301 ;
     RECT  12.384 33.301 33.336 33.539 ;
     RECT  49.968 31.957 49.992 33.635 ;
     RECT  7.488 33.205 11.304 33.779 ;
     RECT  7.488 33.779 10.248 34.211 ;
     RECT  45.6 30.083 46.2 34.259 ;
     RECT  16.128 33.539 33.336 34.643 ;
     RECT  12.576 33.539 15 34.741 ;
     RECT  16.128 34.643 32.904 34.741 ;
     RECT  43.296 34.165 43.32 34.835 ;
     RECT  47.616 33.107 48.264 34.835 ;
     RECT  36.432 31.379 38.088 34.883 ;
     RECT  47.904 34.835 48.264 34.883 ;
     RECT  34.8 32.963 35.304 35.267 ;
     RECT  7.488 34.211 9.528 35.315 ;
     RECT  12.576 34.741 32.904 35.315 ;
     RECT  36.672 34.883 38.088 35.845 ;
     RECT  14.976 35.315 32.904 35.891 ;
     RECT  48.24 34.883 48.264 35.893 ;
     RECT  7.488 35.315 9.432 35.939 ;
     RECT  47.808 35.893 48.264 35.939 ;
     RECT  34.8 35.267 35.112 35.989 ;
     RECT  7.488 35.939 9.096 36.133 ;
     RECT  14.976 35.891 19.464 36.179 ;
     RECT  20.832 35.891 32.904 36.227 ;
     RECT  39.456 33.299 42.216 36.371 ;
     RECT  6.576 36.133 9.096 36.419 ;
     RECT  12.576 35.315 13.656 36.421 ;
     RECT  39.456 36.371 41.784 36.469 ;
     RECT  21.024 36.227 32.904 36.517 ;
     RECT  21.024 36.517 33.048 36.613 ;
     RECT  34.368 35.989 35.112 36.613 ;
     RECT  5.088 32.531 5.448 36.659 ;
     RECT  34.368 36.613 35.208 36.851 ;
     RECT  21.024 36.613 33.24 36.947 ;
     RECT  11.28 33.779 11.304 37.091 ;
     RECT  47.808 35.939 47.832 37.091 ;
     RECT  6.576 36.419 8.856 37.139 ;
     RECT  16.128 36.179 19.464 37.187 ;
     RECT  36.336 35.845 38.088 37.331 ;
     RECT  17.712 37.187 19.464 37.427 ;
     RECT  7.584 37.139 8.856 37.477 ;
     RECT  16.128 37.187 16.584 37.619 ;
     RECT  12.576 36.421 13.752 38.003 ;
     RECT  44.352 37.045 44.376 38.099 ;
     RECT  34.368 36.851 35.112 38.147 ;
     RECT  49.248 35.845 49.272 38.147 ;
     RECT  5.088 36.659 5.112 38.243 ;
     RECT  12.576 38.003 13.656 38.243 ;
     RECT  7.584 37.477 9.048 38.341 ;
     RECT  21.024 36.947 32.712 38.435 ;
     RECT  36.816 37.331 38.088 38.435 ;
     RECT  7.584 38.341 9.144 38.483 ;
     RECT  16.128 37.619 16.392 38.533 ;
     RECT  34.8 38.147 35.112 38.533 ;
     RECT  39.312 36.469 41.784 38.677 ;
     RECT  13.056 38.243 13.656 38.819 ;
     RECT  34.8 38.533 36.024 39.205 ;
     RECT  21.024 38.435 25.464 39.253 ;
     RECT  20.64 39.253 25.464 39.395 ;
     RECT  34.176 39.205 36.024 39.395 ;
     RECT  21.024 39.395 25.464 39.539 ;
     RECT  2.4 26.819 2.712 39.877 ;
     RECT  6.576 37.139 6.6 39.877 ;
     RECT  7.584 38.483 8.856 39.877 ;
     RECT  26.736 38.435 32.712 40.069 ;
     RECT  14.976 36.179 15 40.405 ;
     RECT  21.024 39.539 25.176 40.405 ;
     RECT  34.176 39.395 35.4 40.835 ;
     RECT  45.6 34.259 45.912 40.885 ;
     RECT  45.6 40.885 46.152 41.027 ;
     RECT  14.88 40.405 15 41.029 ;
     RECT  2.4 39.877 3.288 41.075 ;
     RECT  6.576 39.877 8.856 41.075 ;
     RECT  20.832 40.405 25.176 41.171 ;
     RECT  15.984 38.533 16.392 41.173 ;
     RECT  17.712 37.427 18.912 41.173 ;
     RECT  15.984 41.173 18.912 41.315 ;
     RECT  10.896 41.173 10.92 41.317 ;
     RECT  26.688 40.069 32.712 41.509 ;
     RECT  46.896 41.125 46.92 41.651 ;
     RECT  22.464 41.171 25.176 41.699 ;
     RECT  20.832 41.171 21.096 41.939 ;
     RECT  14.736 41.029 15 42.035 ;
     RECT  2.4 41.075 2.712 42.037 ;
     RECT  37.296 38.435 38.088 42.037 ;
     RECT  36.912 42.037 38.088 42.133 ;
     RECT  34.8 40.835 35.4 42.179 ;
     RECT  13.104 38.819 13.656 42.323 ;
     RECT  14.88 42.035 15 42.419 ;
     RECT  2.4 42.037 3.384 42.421 ;
     RECT  22.608 41.699 25.176 42.467 ;
     RECT  26.16 41.509 32.712 42.467 ;
     RECT  43.056 40.837 43.08 42.467 ;
     RECT  26.16 42.467 26.184 42.515 ;
     RECT  10.512 41.317 10.92 42.659 ;
     RECT  19.968 41.941 19.992 42.755 ;
     RECT  22.752 42.467 25.176 42.803 ;
     RECT  39.168 38.677 41.784 42.803 ;
     RECT  13.2 42.323 13.656 42.805 ;
     RECT  21.024 41.939 21.096 42.949 ;
     RECT  15.984 41.315 16.536 42.997 ;
     RECT  17.712 41.315 18.912 42.997 ;
     RECT  21.024 42.949 21.288 43.139 ;
     RECT  36.672 42.133 38.088 43.139 ;
     RECT  15.984 42.997 18.912 43.187 ;
     RECT  13.2 42.805 13.752 43.285 ;
     RECT  45.6 41.027 45.912 43.285 ;
     RECT  17.712 43.187 18.912 43.379 ;
     RECT  27.456 42.467 32.712 43.379 ;
     RECT  33.792 43.189 33.816 43.381 ;
     RECT  39.36 42.803 41.784 43.523 ;
     RECT  21.024 43.139 21.048 43.525 ;
     RECT  14.976 42.419 15 43.907 ;
     RECT  2.4 42.421 4.104 43.955 ;
     RECT  27.456 43.379 31.752 43.955 ;
     RECT  39.888 43.523 41.784 43.955 ;
     RECT  32.88 43.381 33.816 43.957 ;
     RECT  34.8 42.179 35.112 43.957 ;
     RECT  13.2 43.285 13.8 44.245 ;
     RECT  32.88 43.957 35.112 44.291 ;
     RECT  45.6 43.285 46.776 44.339 ;
     RECT  13.2 44.245 14.664 44.341 ;
     RECT  15.984 43.187 16.536 44.437 ;
     RECT  20.544 43.525 21.048 44.483 ;
     RECT  13.056 44.341 14.664 44.581 ;
     RECT  27.456 43.955 29.712 44.627 ;
     RECT  22.8 42.803 25.176 44.915 ;
     RECT  12.288 44.581 14.664 44.963 ;
     RECT  13.2 44.963 14.664 45.011 ;
     RECT  30.864 43.955 31.752 45.011 ;
     RECT  10.896 42.659 10.92 45.059 ;
     RECT  23.712 44.915 25.176 45.251 ;
     RECT  33.84 44.291 35.112 45.397 ;
     RECT  45.6 44.339 46.008 45.397 ;
     RECT  30.864 45.011 31.368 45.587 ;
     RECT  14.64 45.011 14.664 45.589 ;
     RECT  15.984 44.437 16.968 45.589 ;
     RECT  27.792 44.627 29.712 45.635 ;
     RECT  48.72 44.197 48.744 45.635 ;
     RECT  39.984 43.955 41.784 45.779 ;
     RECT  22.512 45.205 22.536 45.971 ;
     RECT  18.336 43.379 18.912 45.973 ;
     RECT  33.792 45.397 35.112 46.021 ;
     RECT  13.2 45.011 13.512 46.069 ;
     RECT  29.04 45.635 29.712 46.211 ;
     RECT  32.928 46.021 35.112 46.211 ;
     RECT  14.64 45.589 16.968 46.259 ;
     RECT  18.24 45.973 18.912 46.259 ;
     RECT  23.808 45.251 25.176 46.405 ;
     RECT  18.336 46.259 18.912 46.451 ;
     RECT  13.2 46.069 13.656 46.501 ;
     RECT  51 15.203 51.312 46.645 ;
     RECT  31.344 45.587 31.368 46.693 ;
     RECT  4.08 43.955 4.104 46.741 ;
     RECT  50.496 46.645 51.312 46.787 ;
     RECT  21.024 44.483 21.048 46.835 ;
     RECT  6.768 41.075 8.856 47.075 ;
     RECT  33.792 46.211 35.112 47.123 ;
     RECT  27.792 45.635 27.816 47.269 ;
     RECT  31.344 46.693 31.56 47.269 ;
     RECT  48.72 46.645 48.744 47.269 ;
     RECT  33.792 47.123 33.816 47.315 ;
     RECT  6.768 47.075 6.792 47.363 ;
     RECT  40.08 45.779 41.784 47.363 ;
     RECT  7.8 47.075 8.856 47.411 ;
     RECT  48.528 47.269 48.744 47.411 ;
     RECT  32.544 46.741 32.568 47.555 ;
     RECT  21.12 47.413 21.144 47.653 ;
     RECT  21.12 47.653 21.24 47.699 ;
     RECT  31.056 47.269 31.56 47.699 ;
     RECT  18.6 46.451 18.912 47.701 ;
     RECT  13.104 46.501 14.52 47.747 ;
     RECT  3.984 46.741 4.104 47.795 ;
     RECT  13.104 47.747 13.608 47.795 ;
     RECT  21.216 47.699 21.24 47.795 ;
     RECT  34.8 47.123 35.112 47.893 ;
     RECT  36.672 43.139 36.696 47.893 ;
     RECT  23.808 46.405 25.848 47.939 ;
     RECT  27.312 47.269 27.816 47.939 ;
     RECT  40.08 47.363 40.512 47.987 ;
     RECT  34.8 47.893 36.696 48.035 ;
     RECT  3.984 47.795 4.008 48.083 ;
     RECT  41.616 47.363 41.64 48.131 ;
     RECT  5.136 47.749 5.16 48.181 ;
     RECT  5.136 48.181 5.4 48.227 ;
     RECT  18.048 47.701 18.912 48.371 ;
     RECT  31.536 47.699 31.56 48.371 ;
     RECT  20.112 47.317 20.136 48.419 ;
     RECT  15.984 46.259 16.968 48.755 ;
     RECT  13.2 47.795 13.608 48.851 ;
     RECT  16.656 48.755 16.968 48.899 ;
     RECT  13.2 48.851 13.512 48.901 ;
     RECT  13.056 48.901 13.512 49.043 ;
     RECT  24 47.939 25.176 49.235 ;
     RECT  45.6 45.397 46.776 49.475 ;
     RECT  36.672 48.035 36.696 49.859 ;
     RECT  48.528 47.411 48.552 50.003 ;
     RECT  27.792 47.939 27.816 50.195 ;
     RECT  32.304 49.429 32.328 50.243 ;
     RECT  20.592 48.949 20.616 50.341 ;
     RECT  16.656 48.899 16.68 50.387 ;
     RECT  20.592 50.341 21.096 50.387 ;
     RECT  21.072 50.387 21.096 50.579 ;
     RECT  7.8 47.411 8.112 50.677 ;
     RECT  43.824 48.805 43.848 50.771 ;
     RECT  38.064 43.139 38.088 50.867 ;
     RECT  5.376 48.227 5.4 51.347 ;
     RECT  6.816 50.677 8.112 51.347 ;
     RECT  43.248 50.773 43.272 51.635 ;
     RECT  2.4 43.955 2.712 51.849 ;
     RECT  7.8 51.347 8.112 51.849 ;
     RECT  13.2 49.043 13.512 51.849 ;
     RECT  18.6 48.371 18.912 51.849 ;
     RECT  24 49.235 24.312 51.849 ;
     RECT  29.4 46.211 29.712 51.849 ;
     RECT  34.8 48.035 35.112 51.849 ;
     RECT  40.2 47.987 40.512 51.849 ;
     RECT  45.6 49.475 45.912 51.849 ;
     RECT  51 46.787 51.312 51.849 ;
     RECT  2.4 51.849 2.52 51.863 ;
     RECT  7.8 51.849 7.92 51.863 ;
     RECT  13.2 51.849 13.32 51.863 ;
     RECT  18.6 51.849 18.72 51.863 ;
     RECT  24 51.849 24.12 51.863 ;
     RECT  29.4 51.849 29.52 51.863 ;
     RECT  34.8 51.849 34.92 51.863 ;
     RECT  40.2 51.849 40.32 51.863 ;
     RECT  45.6 51.849 45.72 51.863 ;
     RECT  51 51.849 51.12 51.863 ;
     RECT  30.264 2.965 31.536 5.557 ;
     RECT  29.088 3.251 29.232 4.405 ;
     RECT  12.816 3.347 13.2 3.925 ;
     RECT  35.496 3.587 35.88 4.165 ;
     RECT  40.512 3.685 41.904 5.029 ;
     RECT  11.544 3.925 13.2 4.789 ;
     RECT  31.56 4.117 33.024 4.739 ;
     RECT  35.496 4.165 36.912 4.693 ;
     RECT  20.568 4.261 21.984 4.789 ;
     RECT  24.312 4.261 25.728 5.269 ;
     RECT  33.048 4.453 34.224 4.739 ;
     RECT  35.928 4.693 36.912 5.747 ;
     RECT  33.888 4.739 34.224 5.317 ;
     RECT  2.712 4.789 3.984 7.091 ;
     RECT  11.544 4.789 12.672 5.749 ;
     RECT  40.632 5.029 41.904 5.077 ;
     RECT  22.008 5.219 23.664 5.747 ;
     RECT  43.992 5.221 44.976 6.275 ;
     RECT  24.408 5.269 25.728 5.603 ;
     RECT  38.904 5.317 40.2 6.037 ;
     RECT  10.56 5.411 11.52 6.901 ;
     RECT  37.656 5.413 38.88 6.899 ;
     RECT  16.056 5.605 17.088 5.843 ;
     RECT  17.112 5.605 18.096 5.843 ;
     RECT  4.008 5.653 5.376 7.091 ;
     RECT  23.088 5.747 23.664 6.421 ;
     RECT  35.64 5.747 36.912 8.003 ;
     RECT  11.544 5.749 12.576 7.667 ;
     RECT  18.912 5.749 20.064 5.845 ;
     RECT  16.056 5.843 18.096 5.987 ;
     RECT  15.672 5.987 18.096 6.421 ;
     RECT  20.088 5.987 21.072 7.957 ;
     RECT  26.76 6.037 28.032 7.285 ;
     RECT  39.096 6.037 40.2 6.227 ;
     RECT  38.904 6.227 40.2 6.899 ;
     RECT  43.896 6.275 44.976 6.323 ;
     RECT  15.672 6.421 16.8 8.485 ;
     RECT  16.824 6.421 18.096 8.005 ;
     RECT  37.656 6.899 37.848 7.237 ;
     RECT  8.856 6.901 9.984 7.381 ;
     RECT  10.008 6.901 11.52 8.435 ;
     RECT  37.8 7.237 37.848 8.245 ;
     RECT  33.168 7.379 33.36 8.485 ;
     RECT  45.912 7.381 47.088 8.003 ;
     RECT  24.888 7.621 25.968 8.869 ;
     RECT  11.544 7.667 12.72 8.435 ;
     RECT  13.896 7.909 15.408 11.029 ;
     RECT  35.4 8.003 36.912 8.531 ;
     RECT  16.824 8.005 18 10.547 ;
     RECT  10.008 8.435 10.536 8.437 ;
     RECT  12.144 8.435 12.72 9.349 ;
     RECT  8.904 8.483 9.984 9.445 ;
     RECT  35.304 8.531 36.912 8.821 ;
     RECT  31.56 8.725 33.024 8.963 ;
     RECT  35.304 8.821 36.576 8.963 ;
     RECT  33.12 8.963 33.168 10.069 ;
     RECT  35.304 8.963 36.768 11.269 ;
     RECT  44.472 9.061 45.6 10.883 ;
     RECT  21 9.155 21.096 10.213 ;
     RECT  5.4 9.491 5.688 10.501 ;
     RECT  15.672 9.731 16.8 12.421 ;
     RECT  12.144 10.067 12.72 10.309 ;
     RECT  21 10.213 21.984 11.701 ;
     RECT  22.008 10.213 23.088 12.227 ;
     RECT  11.352 10.309 12.72 10.547 ;
     RECT  12.528 10.547 12.72 11.413 ;
     RECT  16.824 10.547 18.144 11.749 ;
     RECT  37.8 10.739 37.848 12.085 ;
     RECT  47.904 10.883 48.24 11.365 ;
     RECT  50.88 10.979 51 12.325 ;
     RECT  35.688 11.269 36.768 11.701 ;
     RECT  31.56 11.317 33.072 11.605 ;
     RECT  45.912 11.365 47.232 12.131 ;
     RECT  47.256 11.365 48.24 12.131 ;
     RECT  31.896 11.605 33.072 11.795 ;
     RECT  31.848 11.795 33.072 11.843 ;
     RECT  31.848 11.843 33.12 14.485 ;
     RECT  35.688 11.843 36.768 12.179 ;
     RECT  35.688 12.179 36.816 13.093 ;
     RECT  21.624 12.227 23.088 14.917 ;
     RECT  33.384 12.755 34.368 13.139 ;
     RECT  37.656 12.995 38.136 14.053 ;
     RECT  35.832 13.093 36.816 13.765 ;
     RECT  33.384 13.139 34.8 14.101 ;
     RECT  33.384 14.101 34.704 14.245 ;
     RECT  33.432 14.245 34.704 14.867 ;
     RECT  31.848 14.485 33.024 14.629 ;
     RECT  31.848 14.629 32.976 14.915 ;
     RECT  10.68 14.773 11.952 15.443 ;
     RECT  33.384 14.867 34.704 16.933 ;
     RECT  42.744 14.869 44.256 15.011 ;
     RECT  44.28 14.869 45.6 15.011 ;
     RECT  15.768 14.915 17.232 15.539 ;
     RECT  31.848 14.915 33.024 16.357 ;
     RECT  21.816 14.917 23.088 18.565 ;
     RECT  46.584 15.301 47.616 15.973 ;
     RECT  39.312 15.347 39.648 15.733 ;
     RECT  38.424 15.733 39.648 16.211 ;
     RECT  37.464 16.211 37.704 17.557 ;
     RECT  46.584 16.307 47.568 17.461 ;
     RECT  13.8 16.643 14.832 17.893 ;
     RECT  15.768 17.125 16.944 17.461 ;
     RECT  45.024 17.219 45.6 17.605 ;
     RECT  44.472 17.605 45.6 18.419 ;
     RECT  33.624 18.179 34.656 18.323 ;
     RECT  35.112 18.227 36.096 19.957 ;
     RECT  46.584 18.227 47.568 20.821 ;
     RECT  33.528 18.323 34.656 21.109 ;
     RECT  44.976 18.419 45.6 18.805 ;
     RECT  21.816 18.565 22.944 19.381 ;
     RECT  47.64 19.763 48.504 19.957 ;
     RECT  47.64 19.957 48.672 25.715 ;
     RECT  10.824 20.821 12.24 21.107 ;
     RECT  35.112 20.963 36.096 24.517 ;
     RECT  39.36 21.059 39.648 22.021 ;
     RECT  10.824 21.107 12.288 21.347 ;
     RECT  33.528 21.109 34.56 23.989 ;
     RECT  9.432 21.637 10.8 21.779 ;
     RECT  44.472 22.165 45.6 23.411 ;
     RECT  39.36 22.835 39.648 23.077 ;
     RECT  12.48 23.027 12.72 23.125 ;
     RECT  38.232 23.077 39.648 23.893 ;
     RECT  11.304 23.125 12.72 24.949 ;
     RECT  38.088 24.083 39.12 24.995 ;
     RECT  41.256 24.469 42.672 25.045 ;
     RECT  38.088 24.995 39.36 26.773 ;
     RECT  9.144 25.045 10.224 26.005 ;
     RECT  41.688 25.045 42.672 25.475 ;
     RECT  11.304 25.091 12.72 26.293 ;
     RECT  43.56 25.093 44.928 25.187 ;
     RECT  44.592 25.187 44.928 25.477 ;
     RECT  41.256 25.475 42.672 25.715 ;
     RECT  6.792 25.667 7.8 27.347 ;
     RECT  10.248 25.715 11.28 32.437 ;
     RECT  13.704 25.811 14.688 26.819 ;
     RECT  40.512 25.811 40.632 27.157 ;
     RECT  44.616 25.811 45.6 25.907 ;
     RECT  46.2 26.147 47.616 34.259 ;
     RECT  11.304 26.293 12.528 29.125 ;
     RECT  35.112 26.483 36.336 26.579 ;
     RECT  35.112 26.579 36.672 27.781 ;
     RECT  13.656 26.819 14.688 28.405 ;
     RECT  33.672 27.251 34.656 27.683 ;
     RECT  7.536 27.347 7.8 27.349 ;
     RECT  33.672 27.683 34.8 29.605 ;
     RECT  35.208 27.781 36.672 28.213 ;
     RECT  43.8 27.877 45.072 29.363 ;
     RECT  35.352 28.213 36.672 29.173 ;
     RECT  13.752 28.547 14.976 28.883 ;
     RECT  13.656 28.883 14.976 30.181 ;
     RECT  11.304 29.125 12.288 29.651 ;
     RECT  35.4 29.173 36.672 29.365 ;
     RECT  38.088 29.315 39.264 29.699 ;
     RECT  35.352 29.555 36.432 32.963 ;
     RECT  11.304 29.651 12.576 32.053 ;
     RECT  38.088 29.699 39.36 29.747 ;
     RECT  38.088 29.747 39.456 30.949 ;
     RECT  33.336 30.083 34.8 32.245 ;
     RECT  13.656 30.181 14.784 31.379 ;
     RECT  48.264 30.181 49.344 31.523 ;
     RECT  13.656 31.379 14.976 33.301 ;
     RECT  38.088 31.379 39.456 32.677 ;
     RECT  48.264 31.523 48.36 32.437 ;
     RECT  49.992 31.957 51 33.635 ;
     RECT  33.336 32.245 34.704 32.387 ;
     RECT  33.336 32.387 34.8 34.643 ;
     RECT  11.304 32.675 12.384 33.539 ;
     RECT  38.088 32.677 39.264 33.059 ;
     RECT  42.312 32.723 42.408 33.299 ;
     RECT  35.304 32.963 36.432 34.883 ;
     RECT  38.088 33.059 39.456 36.469 ;
     RECT  42.216 33.299 42.408 34.165 ;
     RECT  11.304 33.539 12.576 37.091 ;
     RECT  15 33.539 16.128 34.741 ;
     RECT  10.248 33.779 11.28 34.211 ;
     RECT  42.216 34.165 43.296 34.835 ;
     RECT  32.904 34.643 34.8 35.989 ;
     RECT  47.808 34.835 47.904 34.883 ;
     RECT  35.304 34.883 36.672 35.267 ;
     RECT  47.808 34.883 48.24 35.893 ;
     RECT  35.112 35.267 36.672 35.845 ;
     RECT  13.656 35.315 14.976 36.421 ;
     RECT  35.112 35.845 36.336 36.613 ;
     RECT  48.264 35.845 49.248 35.939 ;
     RECT  19.464 35.891 20.832 36.227 ;
     RECT  47.832 35.939 49.248 37.091 ;
     RECT  32.904 35.989 34.368 36.517 ;
     RECT  5.448 36.133 6.576 36.659 ;
     RECT  15 36.179 16.128 38.533 ;
     RECT  8.856 36.419 9.048 37.477 ;
     RECT  13.752 36.421 14.976 38.003 ;
     RECT  38.088 36.469 39.312 38.677 ;
     RECT  33.048 36.517 34.368 36.613 ;
     RECT  33.24 36.613 34.368 36.947 ;
     RECT  35.208 36.613 36.336 36.851 ;
     RECT  5.112 36.659 6.576 38.243 ;
     RECT  35.112 36.851 36.336 37.331 ;
     RECT  44.376 37.045 45.6 38.099 ;
     RECT  6.6 37.139 7.584 39.877 ;
     RECT  16.584 37.187 17.712 37.619 ;
     RECT  35.112 37.331 36.816 38.435 ;
     RECT  16.392 37.619 17.712 41.173 ;
     RECT  13.656 38.003 14.976 40.405 ;
     RECT  34.368 38.147 34.8 39.205 ;
     RECT  25.464 38.435 26.736 39.539 ;
     RECT  35.112 38.435 37.296 38.533 ;
     RECT  15 38.533 15.984 43.907 ;
     RECT  36.024 38.533 37.296 39.395 ;
     RECT  38.088 38.677 39.168 42.803 ;
     RECT  32.712 39.205 34.176 40.835 ;
     RECT  20.832 39.395 21.024 40.405 ;
     RECT  25.176 39.539 26.736 40.069 ;
     RECT  25.176 40.069 26.688 41.509 ;
     RECT  13.656 40.405 14.88 41.029 ;
     RECT  41.784 40.837 43.056 42.467 ;
     RECT  45.912 41.027 46.152 41.125 ;
     RECT  13.656 41.029 14.736 42.035 ;
     RECT  2.712 41.075 3.288 42.037 ;
     RECT  45.912 41.125 46.896 41.651 ;
     RECT  21.096 41.171 22.464 41.699 ;
     RECT  16.536 41.315 17.712 42.997 ;
     RECT  25.176 41.509 26.16 42.515 ;
     RECT  21.096 41.699 22.608 42.467 ;
     RECT  20.832 41.939 21.024 41.941 ;
     RECT  18.912 41.941 19.968 42.755 ;
     RECT  19.992 41.941 21.024 42.755 ;
     RECT  13.656 42.035 14.88 42.419 ;
     RECT  35.4 42.037 36.912 42.133 ;
     RECT  35.4 42.133 36.672 42.179 ;
     RECT  13.656 42.419 14.976 42.805 ;
     RECT  21.096 42.467 22.752 42.803 ;
     RECT  26.184 42.467 27.456 42.515 ;
     RECT  20.544 42.755 21.024 43.525 ;
     RECT  21.096 42.803 22.8 42.949 ;
     RECT  38.088 42.803 39.36 43.523 ;
     RECT  13.752 42.805 14.976 43.285 ;
     RECT  21.288 42.949 22.8 43.139 ;
     RECT  36.696 43.139 38.064 49.859 ;
     RECT  16.536 43.187 17.712 43.379 ;
     RECT  32.712 43.189 33.792 43.379 ;
     RECT  33.816 43.189 34.8 43.957 ;
     RECT  13.8 43.285 14.976 43.907 ;
     RECT  16.536 43.379 18.336 44.437 ;
     RECT  31.752 43.379 33.792 43.381 ;
     RECT  31.752 43.381 32.88 44.291 ;
     RECT  13.8 43.907 15.984 44.245 ;
     RECT  2.712 43.955 4.08 46.741 ;
     RECT  29.712 43.955 30.864 45.587 ;
     RECT  14.664 44.245 15.984 45.589 ;
     RECT  33.792 44.291 33.84 45.397 ;
     RECT  46.008 44.339 46.776 45.397 ;
     RECT  16.968 44.437 18.336 45.973 ;
     RECT  10.92 44.581 12.288 44.963 ;
     RECT  22.8 44.915 23.712 45.205 ;
     RECT  13.512 45.011 14.64 46.069 ;
     RECT  21.048 45.205 22.512 45.971 ;
     RECT  22.536 45.205 23.712 45.251 ;
     RECT  22.536 45.251 23.808 45.971 ;
     RECT  27.816 45.635 29.04 46.211 ;
     RECT  48.72 45.635 48.744 46.645 ;
     RECT  21.048 45.971 21.144 46.835 ;
     RECT  16.968 45.973 18.24 46.259 ;
     RECT  13.656 46.069 14.64 46.259 ;
     RECT  32.928 46.211 33.792 46.693 ;
     RECT  13.656 46.259 15.984 46.501 ;
     RECT  16.968 46.259 18.336 46.451 ;
     RECT  16.968 46.451 18.6 47.701 ;
     RECT  14.52 46.501 15.984 47.747 ;
     RECT  31.56 46.693 33.792 46.741 ;
     RECT  2.712 46.741 3.984 48.083 ;
     RECT  31.56 46.741 32.544 47.555 ;
     RECT  32.568 46.741 33.792 47.315 ;
     RECT  21.024 46.835 21.144 47.317 ;
     RECT  6.792 47.075 7.8 47.363 ;
     RECT  33.816 47.123 34.8 47.315 ;
     RECT  25.848 47.269 27.312 47.939 ;
     RECT  29.712 47.269 31.056 47.699 ;
     RECT  18.912 47.317 20.112 48.419 ;
     RECT  20.136 47.317 21.144 47.413 ;
     RECT  40.512 47.363 41.616 48.131 ;
     RECT  20.136 47.413 21.12 47.699 ;
     RECT  20.136 47.699 21.216 47.795 ;
     RECT  16.968 47.701 18.048 48.371 ;
     RECT  4.104 47.749 5.136 47.795 ;
     RECT  4.008 47.795 5.136 48.083 ;
     RECT  13.104 47.795 13.2 48.901 ;
     RECT  20.136 47.795 20.616 48.419 ;
     RECT  20.592 48.419 20.616 48.949 ;
     RECT  5.4 50.677 6.816 51.347 ;
  END
END hbfd_pad_r17x115
END LIBRARY
